VERSION 5.7 ;
  NOWIREEXTENSIONATPIN ON ;
  DIVIDERCHAR "/" ;
  BUSBITCHARS "[]" ;
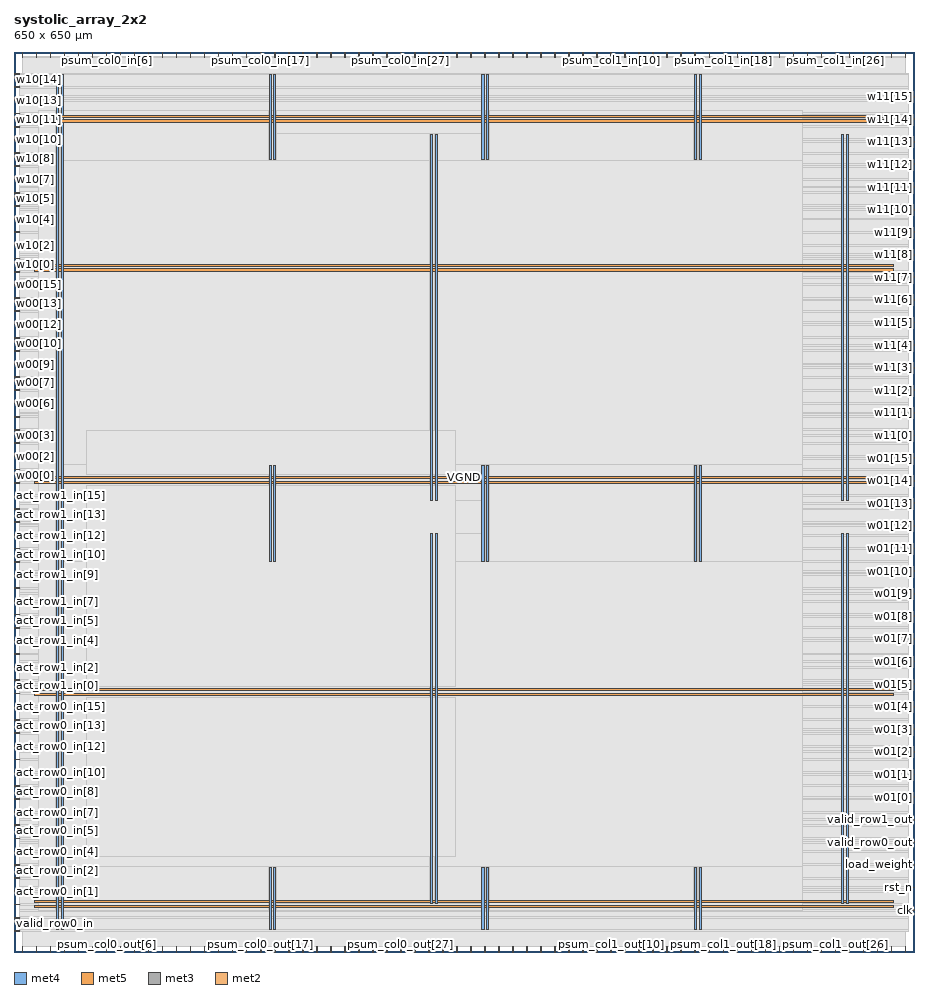
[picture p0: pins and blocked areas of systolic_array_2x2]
MACRO systolic_array_2x2
  CLASS BLOCK ;
  FOREIGN systolic_array_2x2 ;
  ORIGIN 0.000 0.000 ;
  SIZE 650.000 BY 650.000 ;
  PIN VGND
    DIRECTION INOUT ;
    USE GROUND ;
    PORT
      LAYER met4 ;
        RECT 34.000 16.080 35.600 634.000 ;
    END
    PORT
      LAYER met4 ;
        RECT 187.600 16.080 189.200 61.335 ;
    END
    PORT
      LAYER met4 ;
        RECT 187.600 282.105 189.200 351.335 ;
    END
    PORT
      LAYER met4 ;
        RECT 187.600 572.105 189.200 634.000 ;
    END
    PORT
      LAYER met4 ;
        RECT 341.200 16.080 342.800 61.335 ;
    END
    PORT
      LAYER met4 ;
        RECT 341.200 282.105 342.800 351.335 ;
    END
    PORT
      LAYER met4 ;
        RECT 341.200 572.105 342.800 634.000 ;
    END
    PORT
      LAYER met4 ;
        RECT 494.800 16.080 496.400 61.335 ;
    END
    PORT
      LAYER met4 ;
        RECT 494.800 282.105 496.400 351.335 ;
    END
    PORT
      LAYER met4 ;
        RECT 494.800 572.105 496.400 634.000 ;
    END
    PORT
      LAYER met5 ;
        RECT 14.940 35.470 635.040 37.070 ;
    END
    PORT
      LAYER met5 ;
        RECT 14.940 188.650 635.040 190.250 ;
    END
    PORT
      LAYER met5 ;
        RECT 14.940 341.830 635.040 343.430 ;
    END
    PORT
      LAYER met5 ;
        RECT 14.940 495.010 635.040 496.610 ;
    END
    PORT
      LAYER met4 ;
        RECT 304.180 35.120 305.780 302.160 ;
    END
    PORT
      LAYER met4 ;
        RECT 601.340 326.160 602.940 590.480 ;
    END
    PORT
      LAYER met4 ;
        RECT 304.180 326.160 305.780 590.480 ;
    END
    PORT
      LAYER met4 ;
        RECT 601.340 35.120 602.940 302.160 ;
    END
    PORT
      LAYER met5 ;
        RECT 30.700 602.700 635.040 604.300 ;
    END
  END VGND
  PIN VPWR
    DIRECTION INOUT ;
    USE POWER ;
    PORT
      LAYER met4 ;
        RECT 30.700 16.080 32.300 634.000 ;
    END
    PORT
      LAYER met4 ;
        RECT 184.300 16.080 185.900 61.335 ;
    END
    PORT
      LAYER met4 ;
        RECT 184.300 282.105 185.900 351.335 ;
    END
    PORT
      LAYER met4 ;
        RECT 184.300 572.105 185.900 634.000 ;
    END
    PORT
      LAYER met4 ;
        RECT 337.900 16.080 339.500 61.335 ;
    END
    PORT
      LAYER met4 ;
        RECT 337.900 282.105 339.500 351.335 ;
    END
    PORT
      LAYER met4 ;
        RECT 337.900 572.105 339.500 634.000 ;
    END
    PORT
      LAYER met4 ;
        RECT 491.500 16.080 493.100 61.335 ;
    END
    PORT
      LAYER met4 ;
        RECT 491.500 282.105 493.100 351.335 ;
    END
    PORT
      LAYER met4 ;
        RECT 491.500 572.105 493.100 634.000 ;
    END
    PORT
      LAYER met5 ;
        RECT 14.940 32.170 635.040 33.770 ;
    END
    PORT
      LAYER met5 ;
        RECT 14.940 185.350 635.040 186.950 ;
    END
    PORT
      LAYER met5 ;
        RECT 14.940 338.530 635.040 340.130 ;
    END
    PORT
      LAYER met5 ;
        RECT 14.940 491.710 635.040 493.310 ;
    END
    PORT
      LAYER met4 ;
        RECT 300.500 35.120 302.100 302.160 ;
    END
    PORT
      LAYER met4 ;
        RECT 597.660 326.160 599.260 590.480 ;
    END
    PORT
      LAYER met4 ;
        RECT 300.500 326.160 302.100 590.480 ;
    END
    PORT
      LAYER met4 ;
        RECT 597.660 35.120 599.260 302.160 ;
    END
    PORT
      LAYER met5 ;
        RECT 30.700 599.300 635.040 600.900 ;
    END
  END VPWR
  PIN act_row0_in[0]
    DIRECTION INPUT ;
    USE SIGNAL ;
    ANTENNAGATEAREA 0.647700 ;
    ANTENNADIFFAREA 0.434700 ;
    PORT
      LAYER met3 ;
        RECT 0.000 34.040 4.000 34.640 ;
    END
  END act_row0_in[0]
  PIN act_row0_in[10]
    DIRECTION INPUT ;
    USE SIGNAL ;
    ANTENNAGATEAREA 0.647700 ;
    ANTENNADIFFAREA 0.434700 ;
    PORT
      LAYER met3 ;
        RECT 0.000 129.240 4.000 129.840 ;
    END
  END act_row0_in[10]
  PIN act_row0_in[11]
    DIRECTION INPUT ;
    USE SIGNAL ;
    ANTENNAGATEAREA 0.647700 ;
    ANTENNADIFFAREA 0.434700 ;
    PORT
      LAYER met3 ;
        RECT 0.000 138.760 4.000 139.360 ;
    END
  END act_row0_in[11]
  PIN act_row0_in[12]
    DIRECTION INPUT ;
    USE SIGNAL ;
    ANTENNAGATEAREA 0.647700 ;
    ANTENNADIFFAREA 0.434700 ;
    PORT
      LAYER met3 ;
        RECT 0.000 148.280 4.000 148.880 ;
    END
  END act_row0_in[12]
  PIN act_row0_in[13]
    DIRECTION INPUT ;
    USE SIGNAL ;
    ANTENNAGATEAREA 0.647700 ;
    ANTENNADIFFAREA 0.434700 ;
    PORT
      LAYER met3 ;
        RECT 0.000 157.800 4.000 158.400 ;
    END
  END act_row0_in[13]
  PIN act_row0_in[14]
    DIRECTION INPUT ;
    USE SIGNAL ;
    ANTENNAGATEAREA 0.647700 ;
    ANTENNADIFFAREA 0.434700 ;
    PORT
      LAYER met3 ;
        RECT 0.000 167.320 4.000 167.920 ;
    END
  END act_row0_in[14]
  PIN act_row0_in[15]
    DIRECTION INPUT ;
    USE SIGNAL ;
    ANTENNAGATEAREA 0.647700 ;
    ANTENNADIFFAREA 0.434700 ;
    PORT
      LAYER met3 ;
        RECT 0.000 176.840 4.000 177.440 ;
    END
  END act_row0_in[15]
  PIN act_row0_in[1]
    DIRECTION INPUT ;
    USE SIGNAL ;
    ANTENNAGATEAREA 0.647700 ;
    ANTENNADIFFAREA 0.434700 ;
    PORT
      LAYER met3 ;
        RECT 0.000 43.560 4.000 44.160 ;
    END
  END act_row0_in[1]
  PIN act_row0_in[2]
    DIRECTION INPUT ;
    USE SIGNAL ;
    ANTENNAGATEAREA 0.647700 ;
    ANTENNADIFFAREA 0.434700 ;
    PORT
      LAYER met3 ;
        RECT 0.000 53.080 4.000 53.680 ;
    END
  END act_row0_in[2]
  PIN act_row0_in[3]
    DIRECTION INPUT ;
    USE SIGNAL ;
    ANTENNAGATEAREA 0.647700 ;
    ANTENNADIFFAREA 0.434700 ;
    PORT
      LAYER met3 ;
        RECT 0.000 62.600 4.000 63.200 ;
    END
  END act_row0_in[3]
  PIN act_row0_in[4]
    DIRECTION INPUT ;
    USE SIGNAL ;
    ANTENNAGATEAREA 0.647700 ;
    ANTENNADIFFAREA 0.434700 ;
    PORT
      LAYER met3 ;
        RECT 0.000 72.120 4.000 72.720 ;
    END
  END act_row0_in[4]
  PIN act_row0_in[5]
    DIRECTION INPUT ;
    USE SIGNAL ;
    ANTENNAGATEAREA 0.647700 ;
    ANTENNADIFFAREA 0.434700 ;
    PORT
      LAYER met3 ;
        RECT 0.000 81.640 4.000 82.240 ;
    END
  END act_row0_in[5]
  PIN act_row0_in[6]
    DIRECTION INPUT ;
    USE SIGNAL ;
    ANTENNAGATEAREA 0.647700 ;
    ANTENNADIFFAREA 0.434700 ;
    PORT
      LAYER met3 ;
        RECT 0.000 91.160 4.000 91.760 ;
    END
  END act_row0_in[6]
  PIN act_row0_in[7]
    DIRECTION INPUT ;
    USE SIGNAL ;
    ANTENNAGATEAREA 0.647700 ;
    ANTENNADIFFAREA 0.434700 ;
    PORT
      LAYER met3 ;
        RECT 0.000 100.680 4.000 101.280 ;
    END
  END act_row0_in[7]
  PIN act_row0_in[8]
    DIRECTION INPUT ;
    USE SIGNAL ;
    ANTENNAGATEAREA 0.647700 ;
    ANTENNADIFFAREA 0.434700 ;
    PORT
      LAYER met3 ;
        RECT 0.000 110.200 4.000 110.800 ;
    END
  END act_row0_in[8]
  PIN act_row0_in[9]
    DIRECTION INPUT ;
    USE SIGNAL ;
    ANTENNAGATEAREA 0.647700 ;
    ANTENNADIFFAREA 0.434700 ;
    PORT
      LAYER met3 ;
        RECT 0.000 119.720 4.000 120.320 ;
    END
  END act_row0_in[9]
  PIN act_row1_in[0]
    DIRECTION INPUT ;
    USE SIGNAL ;
    ANTENNAGATEAREA 0.631200 ;
    ANTENNADIFFAREA 0.434700 ;
    PORT
      LAYER met3 ;
        RECT 0.000 186.360 4.000 186.960 ;
    END
  END act_row1_in[0]
  PIN act_row1_in[10]
    DIRECTION INPUT ;
    USE SIGNAL ;
    ANTENNAGATEAREA 0.631200 ;
    ANTENNADIFFAREA 0.434700 ;
    PORT
      LAYER met3 ;
        RECT 0.000 281.560 4.000 282.160 ;
    END
  END act_row1_in[10]
  PIN act_row1_in[11]
    DIRECTION INPUT ;
    USE SIGNAL ;
    ANTENNAGATEAREA 0.631200 ;
    ANTENNADIFFAREA 0.434700 ;
    PORT
      LAYER met3 ;
        RECT 0.000 291.080 4.000 291.680 ;
    END
  END act_row1_in[11]
  PIN act_row1_in[12]
    DIRECTION INPUT ;
    USE SIGNAL ;
    ANTENNAGATEAREA 0.631200 ;
    ANTENNADIFFAREA 0.434700 ;
    PORT
      LAYER met3 ;
        RECT 0.000 300.600 4.000 301.200 ;
    END
  END act_row1_in[12]
  PIN act_row1_in[13]
    DIRECTION INPUT ;
    USE SIGNAL ;
    ANTENNAGATEAREA 0.631200 ;
    ANTENNADIFFAREA 0.434700 ;
    PORT
      LAYER met3 ;
        RECT 0.000 310.120 4.000 310.720 ;
    END
  END act_row1_in[13]
  PIN act_row1_in[14]
    DIRECTION INPUT ;
    USE SIGNAL ;
    ANTENNAGATEAREA 0.631200 ;
    ANTENNADIFFAREA 0.434700 ;
    PORT
      LAYER met3 ;
        RECT 0.000 319.640 4.000 320.240 ;
    END
  END act_row1_in[14]
  PIN act_row1_in[15]
    DIRECTION INPUT ;
    USE SIGNAL ;
    ANTENNAGATEAREA 0.560700 ;
    ANTENNADIFFAREA 0.434700 ;
    PORT
      LAYER met3 ;
        RECT 0.000 329.160 4.000 329.760 ;
    END
  END act_row1_in[15]
  PIN act_row1_in[1]
    DIRECTION INPUT ;
    USE SIGNAL ;
    ANTENNAGATEAREA 0.631200 ;
    ANTENNADIFFAREA 0.434700 ;
    PORT
      LAYER met3 ;
        RECT 0.000 195.880 4.000 196.480 ;
    END
  END act_row1_in[1]
  PIN act_row1_in[2]
    DIRECTION INPUT ;
    USE SIGNAL ;
    ANTENNAGATEAREA 0.631200 ;
    ANTENNADIFFAREA 0.434700 ;
    PORT
      LAYER met3 ;
        RECT 0.000 205.400 4.000 206.000 ;
    END
  END act_row1_in[2]
  PIN act_row1_in[3]
    DIRECTION INPUT ;
    USE SIGNAL ;
    ANTENNAGATEAREA 0.631200 ;
    ANTENNADIFFAREA 0.434700 ;
    PORT
      LAYER met3 ;
        RECT 0.000 214.920 4.000 215.520 ;
    END
  END act_row1_in[3]
  PIN act_row1_in[4]
    DIRECTION INPUT ;
    USE SIGNAL ;
    ANTENNAGATEAREA 0.631200 ;
    ANTENNADIFFAREA 0.434700 ;
    PORT
      LAYER met3 ;
        RECT 0.000 224.440 4.000 225.040 ;
    END
  END act_row1_in[4]
  PIN act_row1_in[5]
    DIRECTION INPUT ;
    USE SIGNAL ;
    ANTENNAGATEAREA 0.631200 ;
    ANTENNADIFFAREA 0.434700 ;
    PORT
      LAYER met3 ;
        RECT 0.000 233.960 4.000 234.560 ;
    END
  END act_row1_in[5]
  PIN act_row1_in[6]
    DIRECTION INPUT ;
    USE SIGNAL ;
    ANTENNAGATEAREA 0.631200 ;
    ANTENNADIFFAREA 0.434700 ;
    PORT
      LAYER met3 ;
        RECT 0.000 243.480 4.000 244.080 ;
    END
  END act_row1_in[6]
  PIN act_row1_in[7]
    DIRECTION INPUT ;
    USE SIGNAL ;
    ANTENNAGATEAREA 0.631200 ;
    ANTENNADIFFAREA 0.434700 ;
    PORT
      LAYER met3 ;
        RECT 0.000 253.000 4.000 253.600 ;
    END
  END act_row1_in[7]
  PIN act_row1_in[8]
    DIRECTION INPUT ;
    USE SIGNAL ;
    ANTENNAGATEAREA 0.631200 ;
    ANTENNADIFFAREA 0.434700 ;
    PORT
      LAYER met3 ;
        RECT 0.000 262.520 4.000 263.120 ;
    END
  END act_row1_in[8]
  PIN act_row1_in[9]
    DIRECTION INPUT ;
    USE SIGNAL ;
    ANTENNAGATEAREA 0.631200 ;
    ANTENNADIFFAREA 0.434700 ;
    PORT
      LAYER met3 ;
        RECT 0.000 272.040 4.000 272.640 ;
    END
  END act_row1_in[9]
  PIN clk
    DIRECTION INPUT ;
    USE SIGNAL ;
    ANTENNAGATEAREA 1.286700 ;
    ANTENNADIFFAREA 0.434700 ;
    PORT
      LAYER met3 ;
        RECT 646.000 29.960 650.000 30.560 ;
    END
  END clk
  PIN load_weight
    DIRECTION INPUT ;
    USE SIGNAL ;
    ANTENNAGATEAREA 1.286700 ;
    ANTENNADIFFAREA 0.434700 ;
    PORT
      LAYER met3 ;
        RECT 646.000 62.600 650.000 63.200 ;
    END
  END load_weight
  PIN psum_col0_in[0]
    DIRECTION INPUT ;
    USE SIGNAL ;
    ANTENNAGATEAREA 0.631200 ;
    ANTENNADIFFAREA 0.434700 ;
    PORT
      LAYER met2 ;
        RECT 6.070 646.000 6.350 650.000 ;
    END
  END psum_col0_in[0]
  PIN psum_col0_in[10]
    DIRECTION INPUT ;
    USE SIGNAL ;
    ANTENNAGATEAREA 0.631200 ;
    ANTENNADIFFAREA 0.434700 ;
    PORT
      LAYER met2 ;
        RECT 107.270 646.000 107.550 650.000 ;
    END
  END psum_col0_in[10]
  PIN psum_col0_in[11]
    DIRECTION INPUT ;
    USE SIGNAL ;
    ANTENNAGATEAREA 0.631200 ;
    ANTENNADIFFAREA 0.434700 ;
    PORT
      LAYER met2 ;
        RECT 117.390 646.000 117.670 650.000 ;
    END
  END psum_col0_in[11]
  PIN psum_col0_in[12]
    DIRECTION INPUT ;
    USE SIGNAL ;
    ANTENNAGATEAREA 0.631200 ;
    ANTENNADIFFAREA 0.434700 ;
    PORT
      LAYER met2 ;
        RECT 127.510 646.000 127.790 650.000 ;
    END
  END psum_col0_in[12]
  PIN psum_col0_in[13]
    DIRECTION INPUT ;
    USE SIGNAL ;
    ANTENNAGATEAREA 0.631200 ;
    ANTENNADIFFAREA 0.434700 ;
    PORT
      LAYER met2 ;
        RECT 137.630 646.000 137.910 650.000 ;
    END
  END psum_col0_in[13]
  PIN psum_col0_in[14]
    DIRECTION INPUT ;
    USE SIGNAL ;
    ANTENNAGATEAREA 0.631200 ;
    ANTENNADIFFAREA 0.434700 ;
    PORT
      LAYER met2 ;
        RECT 147.750 646.000 148.030 650.000 ;
    END
  END psum_col0_in[14]
  PIN psum_col0_in[15]
    DIRECTION INPUT ;
    USE SIGNAL ;
    ANTENNAGATEAREA 0.631200 ;
    ANTENNADIFFAREA 0.434700 ;
    PORT
      LAYER met2 ;
        RECT 157.870 646.000 158.150 650.000 ;
    END
  END psum_col0_in[15]
  PIN psum_col0_in[16]
    DIRECTION INPUT ;
    USE SIGNAL ;
    ANTENNAGATEAREA 0.631200 ;
    ANTENNADIFFAREA 0.434700 ;
    PORT
      LAYER met2 ;
        RECT 167.990 646.000 168.270 650.000 ;
    END
  END psum_col0_in[16]
  PIN psum_col0_in[17]
    DIRECTION INPUT ;
    USE SIGNAL ;
    ANTENNAGATEAREA 0.631200 ;
    ANTENNADIFFAREA 0.434700 ;
    PORT
      LAYER met2 ;
        RECT 178.110 646.000 178.390 650.000 ;
    END
  END psum_col0_in[17]
  PIN psum_col0_in[18]
    DIRECTION INPUT ;
    USE SIGNAL ;
    ANTENNAGATEAREA 0.631200 ;
    ANTENNADIFFAREA 0.434700 ;
    PORT
      LAYER met2 ;
        RECT 188.230 646.000 188.510 650.000 ;
    END
  END psum_col0_in[18]
  PIN psum_col0_in[19]
    DIRECTION INPUT ;
    USE SIGNAL ;
    ANTENNAGATEAREA 0.631200 ;
    ANTENNADIFFAREA 0.434700 ;
    PORT
      LAYER met2 ;
        RECT 198.350 646.000 198.630 650.000 ;
    END
  END psum_col0_in[19]
  PIN psum_col0_in[1]
    DIRECTION INPUT ;
    USE SIGNAL ;
    ANTENNAGATEAREA 0.631200 ;
    ANTENNADIFFAREA 0.434700 ;
    PORT
      LAYER met2 ;
        RECT 16.190 646.000 16.470 650.000 ;
    END
  END psum_col0_in[1]
  PIN psum_col0_in[20]
    DIRECTION INPUT ;
    USE SIGNAL ;
    ANTENNAGATEAREA 0.631200 ;
    ANTENNADIFFAREA 0.434700 ;
    PORT
      LAYER met2 ;
        RECT 208.470 646.000 208.750 650.000 ;
    END
  END psum_col0_in[20]
  PIN psum_col0_in[21]
    DIRECTION INPUT ;
    USE SIGNAL ;
    ANTENNAGATEAREA 0.631200 ;
    ANTENNADIFFAREA 0.434700 ;
    PORT
      LAYER met2 ;
        RECT 218.590 646.000 218.870 650.000 ;
    END
  END psum_col0_in[21]
  PIN psum_col0_in[22]
    DIRECTION INPUT ;
    USE SIGNAL ;
    ANTENNAGATEAREA 0.631200 ;
    ANTENNADIFFAREA 0.434700 ;
    PORT
      LAYER met2 ;
        RECT 228.710 646.000 228.990 650.000 ;
    END
  END psum_col0_in[22]
  PIN psum_col0_in[23]
    DIRECTION INPUT ;
    USE SIGNAL ;
    ANTENNAGATEAREA 0.631200 ;
    ANTENNADIFFAREA 0.434700 ;
    PORT
      LAYER met2 ;
        RECT 238.830 646.000 239.110 650.000 ;
    END
  END psum_col0_in[23]
  PIN psum_col0_in[24]
    DIRECTION INPUT ;
    USE SIGNAL ;
    ANTENNAGATEAREA 0.631200 ;
    ANTENNADIFFAREA 0.434700 ;
    PORT
      LAYER met2 ;
        RECT 248.950 646.000 249.230 650.000 ;
    END
  END psum_col0_in[24]
  PIN psum_col0_in[25]
    DIRECTION INPUT ;
    USE SIGNAL ;
    ANTENNAGATEAREA 0.631200 ;
    ANTENNADIFFAREA 0.434700 ;
    PORT
      LAYER met2 ;
        RECT 259.070 646.000 259.350 650.000 ;
    END
  END psum_col0_in[25]
  PIN psum_col0_in[26]
    DIRECTION INPUT ;
    USE SIGNAL ;
    ANTENNAGATEAREA 0.631200 ;
    ANTENNADIFFAREA 0.434700 ;
    PORT
      LAYER met2 ;
        RECT 269.190 646.000 269.470 650.000 ;
    END
  END psum_col0_in[26]
  PIN psum_col0_in[27]
    DIRECTION INPUT ;
    USE SIGNAL ;
    ANTENNAGATEAREA 0.631200 ;
    ANTENNADIFFAREA 0.434700 ;
    PORT
      LAYER met2 ;
        RECT 279.310 646.000 279.590 650.000 ;
    END
  END psum_col0_in[27]
  PIN psum_col0_in[28]
    DIRECTION INPUT ;
    USE SIGNAL ;
    ANTENNAGATEAREA 0.631200 ;
    ANTENNADIFFAREA 0.434700 ;
    PORT
      LAYER met2 ;
        RECT 289.430 646.000 289.710 650.000 ;
    END
  END psum_col0_in[28]
  PIN psum_col0_in[29]
    DIRECTION INPUT ;
    USE SIGNAL ;
    ANTENNAGATEAREA 0.631200 ;
    ANTENNADIFFAREA 0.434700 ;
    PORT
      LAYER met2 ;
        RECT 299.550 646.000 299.830 650.000 ;
    END
  END psum_col0_in[29]
  PIN psum_col0_in[2]
    DIRECTION INPUT ;
    USE SIGNAL ;
    ANTENNAGATEAREA 0.631200 ;
    ANTENNADIFFAREA 0.434700 ;
    PORT
      LAYER met2 ;
        RECT 26.310 646.000 26.590 650.000 ;
    END
  END psum_col0_in[2]
  PIN psum_col0_in[30]
    DIRECTION INPUT ;
    USE SIGNAL ;
    ANTENNAGATEAREA 0.631200 ;
    ANTENNADIFFAREA 0.434700 ;
    PORT
      LAYER met2 ;
        RECT 309.670 646.000 309.950 650.000 ;
    END
  END psum_col0_in[30]
  PIN psum_col0_in[31]
    DIRECTION INPUT ;
    USE SIGNAL ;
    ANTENNAGATEAREA 0.631200 ;
    ANTENNADIFFAREA 0.434700 ;
    PORT
      LAYER met2 ;
        RECT 319.790 646.000 320.070 650.000 ;
    END
  END psum_col0_in[31]
  PIN psum_col0_in[3]
    DIRECTION INPUT ;
    USE SIGNAL ;
    ANTENNAGATEAREA 0.631200 ;
    ANTENNADIFFAREA 0.434700 ;
    PORT
      LAYER met2 ;
        RECT 36.430 646.000 36.710 650.000 ;
    END
  END psum_col0_in[3]
  PIN psum_col0_in[4]
    DIRECTION INPUT ;
    USE SIGNAL ;
    ANTENNAGATEAREA 0.631200 ;
    ANTENNADIFFAREA 0.434700 ;
    PORT
      LAYER met2 ;
        RECT 46.550 646.000 46.830 650.000 ;
    END
  END psum_col0_in[4]
  PIN psum_col0_in[5]
    DIRECTION INPUT ;
    USE SIGNAL ;
    ANTENNAGATEAREA 0.631200 ;
    ANTENNADIFFAREA 0.434700 ;
    PORT
      LAYER met2 ;
        RECT 56.670 646.000 56.950 650.000 ;
    END
  END psum_col0_in[5]
  PIN psum_col0_in[6]
    DIRECTION INPUT ;
    USE SIGNAL ;
    ANTENNAGATEAREA 0.631200 ;
    ANTENNADIFFAREA 0.434700 ;
    PORT
      LAYER met2 ;
        RECT 66.790 646.000 67.070 650.000 ;
    END
  END psum_col0_in[6]
  PIN psum_col0_in[7]
    DIRECTION INPUT ;
    USE SIGNAL ;
    ANTENNAGATEAREA 0.631200 ;
    ANTENNADIFFAREA 0.434700 ;
    PORT
      LAYER met2 ;
        RECT 76.910 646.000 77.190 650.000 ;
    END
  END psum_col0_in[7]
  PIN psum_col0_in[8]
    DIRECTION INPUT ;
    USE SIGNAL ;
    ANTENNAGATEAREA 0.631200 ;
    ANTENNADIFFAREA 0.434700 ;
    PORT
      LAYER met2 ;
        RECT 87.030 646.000 87.310 650.000 ;
    END
  END psum_col0_in[8]
  PIN psum_col0_in[9]
    DIRECTION INPUT ;
    USE SIGNAL ;
    ANTENNAGATEAREA 0.631200 ;
    ANTENNADIFFAREA 0.434700 ;
    PORT
      LAYER met2 ;
        RECT 97.150 646.000 97.430 650.000 ;
    END
  END psum_col0_in[9]
  PIN psum_col0_out[0]
    DIRECTION OUTPUT TRISTATE ;
    USE SIGNAL ;
    ANTENNADIFFAREA 0.795200 ;
    PORT
      LAYER met2 ;
        RECT 6.070 0.000 6.350 4.000 ;
    END
  END psum_col0_out[0]
  PIN psum_col0_out[10]
    DIRECTION OUTPUT TRISTATE ;
    USE SIGNAL ;
    ANTENNADIFFAREA 0.795200 ;
    PORT
      LAYER met2 ;
        RECT 107.270 0.000 107.550 4.000 ;
    END
  END psum_col0_out[10]
  PIN psum_col0_out[11]
    DIRECTION OUTPUT TRISTATE ;
    USE SIGNAL ;
    ANTENNADIFFAREA 0.795200 ;
    PORT
      LAYER met2 ;
        RECT 117.390 0.000 117.670 4.000 ;
    END
  END psum_col0_out[11]
  PIN psum_col0_out[12]
    DIRECTION OUTPUT TRISTATE ;
    USE SIGNAL ;
    ANTENNADIFFAREA 0.795200 ;
    PORT
      LAYER met2 ;
        RECT 127.510 0.000 127.790 4.000 ;
    END
  END psum_col0_out[12]
  PIN psum_col0_out[13]
    DIRECTION OUTPUT TRISTATE ;
    USE SIGNAL ;
    ANTENNADIFFAREA 0.795200 ;
    PORT
      LAYER met2 ;
        RECT 137.630 0.000 137.910 4.000 ;
    END
  END psum_col0_out[13]
  PIN psum_col0_out[14]
    DIRECTION OUTPUT TRISTATE ;
    USE SIGNAL ;
    ANTENNADIFFAREA 0.795200 ;
    PORT
      LAYER met2 ;
        RECT 147.750 0.000 148.030 4.000 ;
    END
  END psum_col0_out[14]
  PIN psum_col0_out[15]
    DIRECTION OUTPUT TRISTATE ;
    USE SIGNAL ;
    ANTENNADIFFAREA 0.795200 ;
    PORT
      LAYER met2 ;
        RECT 157.870 0.000 158.150 4.000 ;
    END
  END psum_col0_out[15]
  PIN psum_col0_out[16]
    DIRECTION OUTPUT TRISTATE ;
    USE SIGNAL ;
    ANTENNADIFFAREA 0.795200 ;
    PORT
      LAYER met2 ;
        RECT 167.990 0.000 168.270 4.000 ;
    END
  END psum_col0_out[16]
  PIN psum_col0_out[17]
    DIRECTION OUTPUT TRISTATE ;
    USE SIGNAL ;
    ANTENNADIFFAREA 0.795200 ;
    PORT
      LAYER met2 ;
        RECT 178.110 0.000 178.390 4.000 ;
    END
  END psum_col0_out[17]
  PIN psum_col0_out[18]
    DIRECTION OUTPUT TRISTATE ;
    USE SIGNAL ;
    ANTENNADIFFAREA 0.795200 ;
    PORT
      LAYER met2 ;
        RECT 188.230 0.000 188.510 4.000 ;
    END
  END psum_col0_out[18]
  PIN psum_col0_out[19]
    DIRECTION OUTPUT TRISTATE ;
    USE SIGNAL ;
    ANTENNADIFFAREA 0.795200 ;
    PORT
      LAYER met2 ;
        RECT 198.350 0.000 198.630 4.000 ;
    END
  END psum_col0_out[19]
  PIN psum_col0_out[1]
    DIRECTION OUTPUT TRISTATE ;
    USE SIGNAL ;
    ANTENNADIFFAREA 0.795200 ;
    PORT
      LAYER met2 ;
        RECT 16.190 0.000 16.470 4.000 ;
    END
  END psum_col0_out[1]
  PIN psum_col0_out[20]
    DIRECTION OUTPUT TRISTATE ;
    USE SIGNAL ;
    ANTENNADIFFAREA 0.795200 ;
    PORT
      LAYER met2 ;
        RECT 208.470 0.000 208.750 4.000 ;
    END
  END psum_col0_out[20]
  PIN psum_col0_out[21]
    DIRECTION OUTPUT TRISTATE ;
    USE SIGNAL ;
    ANTENNADIFFAREA 0.795200 ;
    PORT
      LAYER met2 ;
        RECT 218.590 0.000 218.870 4.000 ;
    END
  END psum_col0_out[21]
  PIN psum_col0_out[22]
    DIRECTION OUTPUT TRISTATE ;
    USE SIGNAL ;
    ANTENNADIFFAREA 0.795200 ;
    PORT
      LAYER met2 ;
        RECT 228.710 0.000 228.990 4.000 ;
    END
  END psum_col0_out[22]
  PIN psum_col0_out[23]
    DIRECTION OUTPUT TRISTATE ;
    USE SIGNAL ;
    ANTENNADIFFAREA 0.795200 ;
    PORT
      LAYER met2 ;
        RECT 238.830 0.000 239.110 4.000 ;
    END
  END psum_col0_out[23]
  PIN psum_col0_out[24]
    DIRECTION OUTPUT TRISTATE ;
    USE SIGNAL ;
    ANTENNADIFFAREA 0.795200 ;
    PORT
      LAYER met2 ;
        RECT 248.950 0.000 249.230 4.000 ;
    END
  END psum_col0_out[24]
  PIN psum_col0_out[25]
    DIRECTION OUTPUT TRISTATE ;
    USE SIGNAL ;
    ANTENNADIFFAREA 0.795200 ;
    PORT
      LAYER met2 ;
        RECT 259.070 0.000 259.350 4.000 ;
    END
  END psum_col0_out[25]
  PIN psum_col0_out[26]
    DIRECTION OUTPUT TRISTATE ;
    USE SIGNAL ;
    ANTENNADIFFAREA 0.795200 ;
    PORT
      LAYER met2 ;
        RECT 269.190 0.000 269.470 4.000 ;
    END
  END psum_col0_out[26]
  PIN psum_col0_out[27]
    DIRECTION OUTPUT TRISTATE ;
    USE SIGNAL ;
    ANTENNADIFFAREA 0.795200 ;
    PORT
      LAYER met2 ;
        RECT 279.310 0.000 279.590 4.000 ;
    END
  END psum_col0_out[27]
  PIN psum_col0_out[28]
    DIRECTION OUTPUT TRISTATE ;
    USE SIGNAL ;
    ANTENNADIFFAREA 0.795200 ;
    PORT
      LAYER met2 ;
        RECT 289.430 0.000 289.710 4.000 ;
    END
  END psum_col0_out[28]
  PIN psum_col0_out[29]
    DIRECTION OUTPUT TRISTATE ;
    USE SIGNAL ;
    ANTENNADIFFAREA 0.795200 ;
    PORT
      LAYER met2 ;
        RECT 299.550 0.000 299.830 4.000 ;
    END
  END psum_col0_out[29]
  PIN psum_col0_out[2]
    DIRECTION OUTPUT TRISTATE ;
    USE SIGNAL ;
    ANTENNADIFFAREA 0.795200 ;
    PORT
      LAYER met2 ;
        RECT 26.310 0.000 26.590 4.000 ;
    END
  END psum_col0_out[2]
  PIN psum_col0_out[30]
    DIRECTION OUTPUT TRISTATE ;
    USE SIGNAL ;
    ANTENNADIFFAREA 0.795200 ;
    PORT
      LAYER met2 ;
        RECT 309.670 0.000 309.950 4.000 ;
    END
  END psum_col0_out[30]
  PIN psum_col0_out[31]
    DIRECTION OUTPUT TRISTATE ;
    USE SIGNAL ;
    ANTENNADIFFAREA 0.795200 ;
    PORT
      LAYER met2 ;
        RECT 319.790 0.000 320.070 4.000 ;
    END
  END psum_col0_out[31]
  PIN psum_col0_out[3]
    DIRECTION OUTPUT TRISTATE ;
    USE SIGNAL ;
    ANTENNADIFFAREA 0.795200 ;
    PORT
      LAYER met2 ;
        RECT 36.430 0.000 36.710 4.000 ;
    END
  END psum_col0_out[3]
  PIN psum_col0_out[4]
    DIRECTION OUTPUT TRISTATE ;
    USE SIGNAL ;
    ANTENNADIFFAREA 0.795200 ;
    PORT
      LAYER met2 ;
        RECT 46.550 0.000 46.830 4.000 ;
    END
  END psum_col0_out[4]
  PIN psum_col0_out[5]
    DIRECTION OUTPUT TRISTATE ;
    USE SIGNAL ;
    ANTENNADIFFAREA 0.795200 ;
    PORT
      LAYER met2 ;
        RECT 56.670 0.000 56.950 4.000 ;
    END
  END psum_col0_out[5]
  PIN psum_col0_out[6]
    DIRECTION OUTPUT TRISTATE ;
    USE SIGNAL ;
    ANTENNADIFFAREA 0.795200 ;
    PORT
      LAYER met2 ;
        RECT 66.790 0.000 67.070 4.000 ;
    END
  END psum_col0_out[6]
  PIN psum_col0_out[7]
    DIRECTION OUTPUT TRISTATE ;
    USE SIGNAL ;
    ANTENNADIFFAREA 0.795200 ;
    PORT
      LAYER met2 ;
        RECT 76.910 0.000 77.190 4.000 ;
    END
  END psum_col0_out[7]
  PIN psum_col0_out[8]
    DIRECTION OUTPUT TRISTATE ;
    USE SIGNAL ;
    ANTENNADIFFAREA 0.795200 ;
    PORT
      LAYER met2 ;
        RECT 87.030 0.000 87.310 4.000 ;
    END
  END psum_col0_out[8]
  PIN psum_col0_out[9]
    DIRECTION OUTPUT TRISTATE ;
    USE SIGNAL ;
    ANTENNADIFFAREA 0.795200 ;
    PORT
      LAYER met2 ;
        RECT 97.150 0.000 97.430 4.000 ;
    END
  END psum_col0_out[9]
  PIN psum_col1_in[0]
    DIRECTION INPUT ;
    USE SIGNAL ;
    ANTENNAGATEAREA 0.631200 ;
    ANTENNADIFFAREA 0.434700 ;
    PORT
      LAYER met2 ;
        RECT 329.910 646.000 330.190 650.000 ;
    END
  END psum_col1_in[0]
  PIN psum_col1_in[10]
    DIRECTION INPUT ;
    USE SIGNAL ;
    ANTENNAGATEAREA 0.631200 ;
    ANTENNADIFFAREA 0.434700 ;
    PORT
      LAYER met2 ;
        RECT 431.110 646.000 431.390 650.000 ;
    END
  END psum_col1_in[10]
  PIN psum_col1_in[11]
    DIRECTION INPUT ;
    USE SIGNAL ;
    ANTENNAGATEAREA 0.631200 ;
    ANTENNADIFFAREA 0.434700 ;
    PORT
      LAYER met2 ;
        RECT 441.230 646.000 441.510 650.000 ;
    END
  END psum_col1_in[11]
  PIN psum_col1_in[12]
    DIRECTION INPUT ;
    USE SIGNAL ;
    ANTENNAGATEAREA 0.631200 ;
    ANTENNADIFFAREA 0.434700 ;
    PORT
      LAYER met2 ;
        RECT 451.350 646.000 451.630 650.000 ;
    END
  END psum_col1_in[12]
  PIN psum_col1_in[13]
    DIRECTION INPUT ;
    USE SIGNAL ;
    ANTENNAGATEAREA 0.631200 ;
    ANTENNADIFFAREA 0.434700 ;
    PORT
      LAYER met2 ;
        RECT 461.470 646.000 461.750 650.000 ;
    END
  END psum_col1_in[13]
  PIN psum_col1_in[14]
    DIRECTION INPUT ;
    USE SIGNAL ;
    ANTENNAGATEAREA 0.631200 ;
    ANTENNADIFFAREA 0.434700 ;
    PORT
      LAYER met2 ;
        RECT 471.590 646.000 471.870 650.000 ;
    END
  END psum_col1_in[14]
  PIN psum_col1_in[15]
    DIRECTION INPUT ;
    USE SIGNAL ;
    ANTENNAGATEAREA 0.631200 ;
    ANTENNADIFFAREA 0.434700 ;
    PORT
      LAYER met2 ;
        RECT 481.710 646.000 481.990 650.000 ;
    END
  END psum_col1_in[15]
  PIN psum_col1_in[16]
    DIRECTION INPUT ;
    USE SIGNAL ;
    ANTENNAGATEAREA 0.631200 ;
    ANTENNADIFFAREA 0.434700 ;
    PORT
      LAYER met2 ;
        RECT 491.830 646.000 492.110 650.000 ;
    END
  END psum_col1_in[16]
  PIN psum_col1_in[17]
    DIRECTION INPUT ;
    USE SIGNAL ;
    ANTENNAGATEAREA 0.631200 ;
    ANTENNADIFFAREA 0.434700 ;
    PORT
      LAYER met2 ;
        RECT 501.950 646.000 502.230 650.000 ;
    END
  END psum_col1_in[17]
  PIN psum_col1_in[18]
    DIRECTION INPUT ;
    USE SIGNAL ;
    ANTENNAGATEAREA 0.631200 ;
    ANTENNADIFFAREA 0.434700 ;
    PORT
      LAYER met2 ;
        RECT 512.070 646.000 512.350 650.000 ;
    END
  END psum_col1_in[18]
  PIN psum_col1_in[19]
    DIRECTION INPUT ;
    USE SIGNAL ;
    ANTENNAGATEAREA 0.631200 ;
    ANTENNADIFFAREA 0.434700 ;
    PORT
      LAYER met2 ;
        RECT 522.190 646.000 522.470 650.000 ;
    END
  END psum_col1_in[19]
  PIN psum_col1_in[1]
    DIRECTION INPUT ;
    USE SIGNAL ;
    ANTENNAGATEAREA 0.631200 ;
    ANTENNADIFFAREA 0.434700 ;
    PORT
      LAYER met2 ;
        RECT 340.030 646.000 340.310 650.000 ;
    END
  END psum_col1_in[1]
  PIN psum_col1_in[20]
    DIRECTION INPUT ;
    USE SIGNAL ;
    ANTENNAGATEAREA 0.560700 ;
    ANTENNADIFFAREA 0.434700 ;
    PORT
      LAYER met2 ;
        RECT 532.310 646.000 532.590 650.000 ;
    END
  END psum_col1_in[20]
  PIN psum_col1_in[21]
    DIRECTION INPUT ;
    USE SIGNAL ;
    ANTENNAGATEAREA 0.560700 ;
    ANTENNADIFFAREA 0.434700 ;
    PORT
      LAYER met2 ;
        RECT 542.430 646.000 542.710 650.000 ;
    END
  END psum_col1_in[21]
  PIN psum_col1_in[22]
    DIRECTION INPUT ;
    USE SIGNAL ;
    ANTENNAGATEAREA 0.560700 ;
    ANTENNADIFFAREA 0.434700 ;
    PORT
      LAYER met2 ;
        RECT 552.550 646.000 552.830 650.000 ;
    END
  END psum_col1_in[22]
  PIN psum_col1_in[23]
    DIRECTION INPUT ;
    USE SIGNAL ;
    ANTENNAGATEAREA 0.560700 ;
    ANTENNADIFFAREA 0.434700 ;
    PORT
      LAYER met2 ;
        RECT 562.670 646.000 562.950 650.000 ;
    END
  END psum_col1_in[23]
  PIN psum_col1_in[24]
    DIRECTION INPUT ;
    USE SIGNAL ;
    ANTENNAGATEAREA 0.560700 ;
    ANTENNADIFFAREA 0.434700 ;
    PORT
      LAYER met2 ;
        RECT 572.790 646.000 573.070 650.000 ;
    END
  END psum_col1_in[24]
  PIN psum_col1_in[25]
    DIRECTION INPUT ;
    USE SIGNAL ;
    ANTENNAGATEAREA 0.560700 ;
    ANTENNADIFFAREA 0.434700 ;
    PORT
      LAYER met2 ;
        RECT 582.910 646.000 583.190 650.000 ;
    END
  END psum_col1_in[25]
  PIN psum_col1_in[26]
    DIRECTION INPUT ;
    USE SIGNAL ;
    ANTENNAGATEAREA 0.560700 ;
    ANTENNADIFFAREA 0.434700 ;
    PORT
      LAYER met2 ;
        RECT 593.030 646.000 593.310 650.000 ;
    END
  END psum_col1_in[26]
  PIN psum_col1_in[27]
    DIRECTION INPUT ;
    USE SIGNAL ;
    ANTENNAGATEAREA 0.560700 ;
    ANTENNADIFFAREA 0.434700 ;
    PORT
      LAYER met2 ;
        RECT 603.150 646.000 603.430 650.000 ;
    END
  END psum_col1_in[27]
  PIN psum_col1_in[28]
    DIRECTION INPUT ;
    USE SIGNAL ;
    ANTENNAGATEAREA 0.647700 ;
    ANTENNADIFFAREA 0.434700 ;
    PORT
      LAYER met2 ;
        RECT 613.270 646.000 613.550 650.000 ;
    END
  END psum_col1_in[28]
  PIN psum_col1_in[29]
    DIRECTION INPUT ;
    USE SIGNAL ;
    ANTENNAGATEAREA 0.647700 ;
    ANTENNADIFFAREA 0.434700 ;
    PORT
      LAYER met2 ;
        RECT 623.390 646.000 623.670 650.000 ;
    END
  END psum_col1_in[29]
  PIN psum_col1_in[2]
    DIRECTION INPUT ;
    USE SIGNAL ;
    ANTENNAGATEAREA 0.631200 ;
    ANTENNADIFFAREA 0.434700 ;
    PORT
      LAYER met2 ;
        RECT 350.150 646.000 350.430 650.000 ;
    END
  END psum_col1_in[2]
  PIN psum_col1_in[30]
    DIRECTION INPUT ;
    USE SIGNAL ;
    ANTENNAGATEAREA 0.647700 ;
    ANTENNADIFFAREA 0.434700 ;
    PORT
      LAYER met2 ;
        RECT 633.510 646.000 633.790 650.000 ;
    END
  END psum_col1_in[30]
  PIN psum_col1_in[31]
    DIRECTION INPUT ;
    USE SIGNAL ;
    ANTENNAGATEAREA 0.647700 ;
    ANTENNADIFFAREA 0.434700 ;
    PORT
      LAYER met2 ;
        RECT 643.630 646.000 643.910 650.000 ;
    END
  END psum_col1_in[31]
  PIN psum_col1_in[3]
    DIRECTION INPUT ;
    USE SIGNAL ;
    ANTENNAGATEAREA 0.631200 ;
    ANTENNADIFFAREA 0.434700 ;
    PORT
      LAYER met2 ;
        RECT 360.270 646.000 360.550 650.000 ;
    END
  END psum_col1_in[3]
  PIN psum_col1_in[4]
    DIRECTION INPUT ;
    USE SIGNAL ;
    ANTENNAGATEAREA 0.631200 ;
    ANTENNADIFFAREA 0.434700 ;
    PORT
      LAYER met2 ;
        RECT 370.390 646.000 370.670 650.000 ;
    END
  END psum_col1_in[4]
  PIN psum_col1_in[5]
    DIRECTION INPUT ;
    USE SIGNAL ;
    ANTENNAGATEAREA 0.631200 ;
    ANTENNADIFFAREA 0.434700 ;
    PORT
      LAYER met2 ;
        RECT 380.510 646.000 380.790 650.000 ;
    END
  END psum_col1_in[5]
  PIN psum_col1_in[6]
    DIRECTION INPUT ;
    USE SIGNAL ;
    ANTENNAGATEAREA 0.631200 ;
    ANTENNADIFFAREA 0.434700 ;
    PORT
      LAYER met2 ;
        RECT 390.630 646.000 390.910 650.000 ;
    END
  END psum_col1_in[6]
  PIN psum_col1_in[7]
    DIRECTION INPUT ;
    USE SIGNAL ;
    ANTENNAGATEAREA 0.631200 ;
    ANTENNADIFFAREA 0.434700 ;
    PORT
      LAYER met2 ;
        RECT 400.750 646.000 401.030 650.000 ;
    END
  END psum_col1_in[7]
  PIN psum_col1_in[8]
    DIRECTION INPUT ;
    USE SIGNAL ;
    ANTENNAGATEAREA 0.631200 ;
    ANTENNADIFFAREA 0.434700 ;
    PORT
      LAYER met2 ;
        RECT 410.870 646.000 411.150 650.000 ;
    END
  END psum_col1_in[8]
  PIN psum_col1_in[9]
    DIRECTION INPUT ;
    USE SIGNAL ;
    ANTENNAGATEAREA 0.631200 ;
    ANTENNADIFFAREA 0.434700 ;
    PORT
      LAYER met2 ;
        RECT 420.990 646.000 421.270 650.000 ;
    END
  END psum_col1_in[9]
  PIN psum_col1_out[0]
    DIRECTION OUTPUT TRISTATE ;
    USE SIGNAL ;
    ANTENNADIFFAREA 0.795200 ;
    PORT
      LAYER met2 ;
        RECT 329.910 0.000 330.190 4.000 ;
    END
  END psum_col1_out[0]
  PIN psum_col1_out[10]
    DIRECTION OUTPUT TRISTATE ;
    USE SIGNAL ;
    ANTENNADIFFAREA 0.795200 ;
    PORT
      LAYER met2 ;
        RECT 431.110 0.000 431.390 4.000 ;
    END
  END psum_col1_out[10]
  PIN psum_col1_out[11]
    DIRECTION OUTPUT TRISTATE ;
    USE SIGNAL ;
    ANTENNADIFFAREA 0.795200 ;
    PORT
      LAYER met2 ;
        RECT 441.230 0.000 441.510 4.000 ;
    END
  END psum_col1_out[11]
  PIN psum_col1_out[12]
    DIRECTION OUTPUT TRISTATE ;
    USE SIGNAL ;
    ANTENNADIFFAREA 0.795200 ;
    PORT
      LAYER met2 ;
        RECT 451.350 0.000 451.630 4.000 ;
    END
  END psum_col1_out[12]
  PIN psum_col1_out[13]
    DIRECTION OUTPUT TRISTATE ;
    USE SIGNAL ;
    ANTENNADIFFAREA 0.795200 ;
    PORT
      LAYER met2 ;
        RECT 461.470 0.000 461.750 4.000 ;
    END
  END psum_col1_out[13]
  PIN psum_col1_out[14]
    DIRECTION OUTPUT TRISTATE ;
    USE SIGNAL ;
    ANTENNADIFFAREA 0.795200 ;
    PORT
      LAYER met2 ;
        RECT 471.590 0.000 471.870 4.000 ;
    END
  END psum_col1_out[14]
  PIN psum_col1_out[15]
    DIRECTION OUTPUT TRISTATE ;
    USE SIGNAL ;
    ANTENNADIFFAREA 0.795200 ;
    PORT
      LAYER met2 ;
        RECT 481.710 0.000 481.990 4.000 ;
    END
  END psum_col1_out[15]
  PIN psum_col1_out[16]
    DIRECTION OUTPUT TRISTATE ;
    USE SIGNAL ;
    ANTENNADIFFAREA 0.795200 ;
    PORT
      LAYER met2 ;
        RECT 491.830 0.000 492.110 4.000 ;
    END
  END psum_col1_out[16]
  PIN psum_col1_out[17]
    DIRECTION OUTPUT TRISTATE ;
    USE SIGNAL ;
    ANTENNADIFFAREA 0.795200 ;
    PORT
      LAYER met2 ;
        RECT 501.950 0.000 502.230 4.000 ;
    END
  END psum_col1_out[17]
  PIN psum_col1_out[18]
    DIRECTION OUTPUT TRISTATE ;
    USE SIGNAL ;
    ANTENNADIFFAREA 0.795200 ;
    PORT
      LAYER met2 ;
        RECT 512.070 0.000 512.350 4.000 ;
    END
  END psum_col1_out[18]
  PIN psum_col1_out[19]
    DIRECTION OUTPUT TRISTATE ;
    USE SIGNAL ;
    ANTENNADIFFAREA 0.795200 ;
    PORT
      LAYER met2 ;
        RECT 522.190 0.000 522.470 4.000 ;
    END
  END psum_col1_out[19]
  PIN psum_col1_out[1]
    DIRECTION OUTPUT TRISTATE ;
    USE SIGNAL ;
    ANTENNADIFFAREA 0.795200 ;
    PORT
      LAYER met2 ;
        RECT 340.030 0.000 340.310 4.000 ;
    END
  END psum_col1_out[1]
  PIN psum_col1_out[20]
    DIRECTION OUTPUT TRISTATE ;
    USE SIGNAL ;
    ANTENNADIFFAREA 0.795200 ;
    PORT
      LAYER met2 ;
        RECT 532.310 0.000 532.590 4.000 ;
    END
  END psum_col1_out[20]
  PIN psum_col1_out[21]
    DIRECTION OUTPUT TRISTATE ;
    USE SIGNAL ;
    ANTENNADIFFAREA 0.795200 ;
    PORT
      LAYER met2 ;
        RECT 542.430 0.000 542.710 4.000 ;
    END
  END psum_col1_out[21]
  PIN psum_col1_out[22]
    DIRECTION OUTPUT TRISTATE ;
    USE SIGNAL ;
    ANTENNADIFFAREA 0.795200 ;
    PORT
      LAYER met2 ;
        RECT 552.550 0.000 552.830 4.000 ;
    END
  END psum_col1_out[22]
  PIN psum_col1_out[23]
    DIRECTION OUTPUT TRISTATE ;
    USE SIGNAL ;
    ANTENNADIFFAREA 0.795200 ;
    PORT
      LAYER met2 ;
        RECT 562.670 0.000 562.950 4.000 ;
    END
  END psum_col1_out[23]
  PIN psum_col1_out[24]
    DIRECTION OUTPUT TRISTATE ;
    USE SIGNAL ;
    ANTENNADIFFAREA 0.795200 ;
    PORT
      LAYER met2 ;
        RECT 572.790 0.000 573.070 4.000 ;
    END
  END psum_col1_out[24]
  PIN psum_col1_out[25]
    DIRECTION OUTPUT TRISTATE ;
    USE SIGNAL ;
    ANTENNADIFFAREA 0.795200 ;
    PORT
      LAYER met2 ;
        RECT 582.910 0.000 583.190 4.000 ;
    END
  END psum_col1_out[25]
  PIN psum_col1_out[26]
    DIRECTION OUTPUT TRISTATE ;
    USE SIGNAL ;
    ANTENNADIFFAREA 0.795200 ;
    PORT
      LAYER met2 ;
        RECT 593.030 0.000 593.310 4.000 ;
    END
  END psum_col1_out[26]
  PIN psum_col1_out[27]
    DIRECTION OUTPUT TRISTATE ;
    USE SIGNAL ;
    ANTENNADIFFAREA 0.795200 ;
    PORT
      LAYER met2 ;
        RECT 603.150 0.000 603.430 4.000 ;
    END
  END psum_col1_out[27]
  PIN psum_col1_out[28]
    DIRECTION OUTPUT TRISTATE ;
    USE SIGNAL ;
    ANTENNADIFFAREA 0.795200 ;
    PORT
      LAYER met2 ;
        RECT 613.270 0.000 613.550 4.000 ;
    END
  END psum_col1_out[28]
  PIN psum_col1_out[29]
    DIRECTION OUTPUT TRISTATE ;
    USE SIGNAL ;
    ANTENNADIFFAREA 0.795200 ;
    PORT
      LAYER met2 ;
        RECT 623.390 0.000 623.670 4.000 ;
    END
  END psum_col1_out[29]
  PIN psum_col1_out[2]
    DIRECTION OUTPUT TRISTATE ;
    USE SIGNAL ;
    ANTENNADIFFAREA 0.795200 ;
    PORT
      LAYER met2 ;
        RECT 350.150 0.000 350.430 4.000 ;
    END
  END psum_col1_out[2]
  PIN psum_col1_out[30]
    DIRECTION OUTPUT TRISTATE ;
    USE SIGNAL ;
    ANTENNADIFFAREA 0.795200 ;
    PORT
      LAYER met2 ;
        RECT 633.510 0.000 633.790 4.000 ;
    END
  END psum_col1_out[30]
  PIN psum_col1_out[31]
    DIRECTION OUTPUT TRISTATE ;
    USE SIGNAL ;
    ANTENNADIFFAREA 0.795200 ;
    PORT
      LAYER met2 ;
        RECT 643.630 0.000 643.910 4.000 ;
    END
  END psum_col1_out[31]
  PIN psum_col1_out[3]
    DIRECTION OUTPUT TRISTATE ;
    USE SIGNAL ;
    ANTENNADIFFAREA 0.795200 ;
    PORT
      LAYER met2 ;
        RECT 360.270 0.000 360.550 4.000 ;
    END
  END psum_col1_out[3]
  PIN psum_col1_out[4]
    DIRECTION OUTPUT TRISTATE ;
    USE SIGNAL ;
    ANTENNADIFFAREA 0.795200 ;
    PORT
      LAYER met2 ;
        RECT 370.390 0.000 370.670 4.000 ;
    END
  END psum_col1_out[4]
  PIN psum_col1_out[5]
    DIRECTION OUTPUT TRISTATE ;
    USE SIGNAL ;
    ANTENNADIFFAREA 0.795200 ;
    PORT
      LAYER met2 ;
        RECT 380.510 0.000 380.790 4.000 ;
    END
  END psum_col1_out[5]
  PIN psum_col1_out[6]
    DIRECTION OUTPUT TRISTATE ;
    USE SIGNAL ;
    ANTENNADIFFAREA 0.795200 ;
    PORT
      LAYER met2 ;
        RECT 390.630 0.000 390.910 4.000 ;
    END
  END psum_col1_out[6]
  PIN psum_col1_out[7]
    DIRECTION OUTPUT TRISTATE ;
    USE SIGNAL ;
    ANTENNADIFFAREA 0.795200 ;
    PORT
      LAYER met2 ;
        RECT 400.750 0.000 401.030 4.000 ;
    END
  END psum_col1_out[7]
  PIN psum_col1_out[8]
    DIRECTION OUTPUT TRISTATE ;
    USE SIGNAL ;
    ANTENNADIFFAREA 0.795200 ;
    PORT
      LAYER met2 ;
        RECT 410.870 0.000 411.150 4.000 ;
    END
  END psum_col1_out[8]
  PIN psum_col1_out[9]
    DIRECTION OUTPUT TRISTATE ;
    USE SIGNAL ;
    ANTENNADIFFAREA 0.795200 ;
    PORT
      LAYER met2 ;
        RECT 420.990 0.000 421.270 4.000 ;
    END
  END psum_col1_out[9]
  PIN rst_n
    DIRECTION INPUT ;
    USE SIGNAL ;
    ANTENNAGATEAREA 1.286700 ;
    ANTENNADIFFAREA 0.434700 ;
    PORT
      LAYER met3 ;
        RECT 646.000 46.280 650.000 46.880 ;
    END
  END rst_n
  PIN valid_row0_in
    DIRECTION INPUT ;
    USE SIGNAL ;
    ANTENNAGATEAREA 0.647700 ;
    ANTENNADIFFAREA 0.434700 ;
    PORT
      LAYER met3 ;
        RECT 0.000 15.000 4.000 15.600 ;
    END
  END valid_row0_in
  PIN valid_row0_out
    DIRECTION OUTPUT TRISTATE ;
    USE SIGNAL ;
    ANTENNADIFFAREA 0.795200 ;
    PORT
      LAYER met3 ;
        RECT 646.000 78.920 650.000 79.520 ;
    END
  END valid_row0_out
  PIN valid_row1_in
    DIRECTION INPUT ;
    USE SIGNAL ;
    ANTENNAGATEAREA 0.647700 ;
    ANTENNADIFFAREA 0.434700 ;
    PORT
      LAYER met3 ;
        RECT 0.000 24.520 4.000 25.120 ;
    END
  END valid_row1_in
  PIN valid_row1_out
    DIRECTION OUTPUT TRISTATE ;
    USE SIGNAL ;
    ANTENNADIFFAREA 0.795200 ;
    PORT
      LAYER met3 ;
        RECT 646.000 95.240 650.000 95.840 ;
    END
  END valid_row1_out
  PIN w00[0]
    DIRECTION INPUT ;
    USE SIGNAL ;
    ANTENNAGATEAREA 0.631200 ;
    ANTENNADIFFAREA 0.434700 ;
    PORT
      LAYER met3 ;
        RECT 0.000 338.680 4.000 339.280 ;
    END
  END w00[0]
  PIN w00[10]
    DIRECTION INPUT ;
    USE SIGNAL ;
    ANTENNAGATEAREA 0.631200 ;
    ANTENNADIFFAREA 0.434700 ;
    PORT
      LAYER met3 ;
        RECT 0.000 433.880 4.000 434.480 ;
    END
  END w00[10]
  PIN w00[11]
    DIRECTION INPUT ;
    USE SIGNAL ;
    ANTENNAGATEAREA 0.631200 ;
    ANTENNADIFFAREA 0.434700 ;
    PORT
      LAYER met3 ;
        RECT 0.000 443.400 4.000 444.000 ;
    END
  END w00[11]
  PIN w00[12]
    DIRECTION INPUT ;
    USE SIGNAL ;
    ANTENNAGATEAREA 0.631200 ;
    ANTENNADIFFAREA 0.434700 ;
    PORT
      LAYER met3 ;
        RECT 0.000 452.920 4.000 453.520 ;
    END
  END w00[12]
  PIN w00[13]
    DIRECTION INPUT ;
    USE SIGNAL ;
    ANTENNAGATEAREA 0.631200 ;
    ANTENNADIFFAREA 0.434700 ;
    PORT
      LAYER met3 ;
        RECT 0.000 462.440 4.000 463.040 ;
    END
  END w00[13]
  PIN w00[14]
    DIRECTION INPUT ;
    USE SIGNAL ;
    ANTENNAGATEAREA 0.631200 ;
    ANTENNADIFFAREA 0.434700 ;
    PORT
      LAYER met3 ;
        RECT 0.000 471.960 4.000 472.560 ;
    END
  END w00[14]
  PIN w00[15]
    DIRECTION INPUT ;
    USE SIGNAL ;
    ANTENNAGATEAREA 0.631200 ;
    ANTENNADIFFAREA 0.434700 ;
    PORT
      LAYER met3 ;
        RECT 0.000 481.480 4.000 482.080 ;
    END
  END w00[15]
  PIN w00[1]
    DIRECTION INPUT ;
    USE SIGNAL ;
    ANTENNAGATEAREA 0.631200 ;
    ANTENNADIFFAREA 0.434700 ;
    PORT
      LAYER met3 ;
        RECT 0.000 348.200 4.000 348.800 ;
    END
  END w00[1]
  PIN w00[2]
    DIRECTION INPUT ;
    USE SIGNAL ;
    ANTENNAGATEAREA 0.631200 ;
    ANTENNADIFFAREA 0.434700 ;
    PORT
      LAYER met3 ;
        RECT 0.000 357.720 4.000 358.320 ;
    END
  END w00[2]
  PIN w00[3]
    DIRECTION INPUT ;
    USE SIGNAL ;
    ANTENNAGATEAREA 0.631200 ;
    ANTENNADIFFAREA 0.434700 ;
    PORT
      LAYER met3 ;
        RECT 0.000 367.240 4.000 367.840 ;
    END
  END w00[3]
  PIN w00[4]
    DIRECTION INPUT ;
    USE SIGNAL ;
    ANTENNAGATEAREA 0.631200 ;
    ANTENNADIFFAREA 0.434700 ;
    PORT
      LAYER met3 ;
        RECT 0.000 376.760 4.000 377.360 ;
    END
  END w00[4]
  PIN w00[5]
    DIRECTION INPUT ;
    USE SIGNAL ;
    ANTENNAGATEAREA 0.631200 ;
    ANTENNADIFFAREA 0.434700 ;
    PORT
      LAYER met3 ;
        RECT 0.000 386.280 4.000 386.880 ;
    END
  END w00[5]
  PIN w00[6]
    DIRECTION INPUT ;
    USE SIGNAL ;
    ANTENNAGATEAREA 0.631200 ;
    ANTENNADIFFAREA 0.434700 ;
    PORT
      LAYER met3 ;
        RECT 0.000 395.800 4.000 396.400 ;
    END
  END w00[6]
  PIN w00[7]
    DIRECTION INPUT ;
    USE SIGNAL ;
    ANTENNAGATEAREA 0.631200 ;
    ANTENNADIFFAREA 0.434700 ;
    PORT
      LAYER met3 ;
        RECT 0.000 405.320 4.000 405.920 ;
    END
  END w00[7]
  PIN w00[8]
    DIRECTION INPUT ;
    USE SIGNAL ;
    ANTENNAGATEAREA 0.631200 ;
    ANTENNADIFFAREA 0.434700 ;
    PORT
      LAYER met3 ;
        RECT 0.000 414.840 4.000 415.440 ;
    END
  END w00[8]
  PIN w00[9]
    DIRECTION INPUT ;
    USE SIGNAL ;
    ANTENNAGATEAREA 0.631200 ;
    ANTENNADIFFAREA 0.434700 ;
    PORT
      LAYER met3 ;
        RECT 0.000 424.360 4.000 424.960 ;
    END
  END w00[9]
  PIN w01[0]
    DIRECTION INPUT ;
    USE SIGNAL ;
    ANTENNAGATEAREA 0.682200 ;
    ANTENNADIFFAREA 0.434700 ;
    PORT
      LAYER met3 ;
        RECT 646.000 111.560 650.000 112.160 ;
    END
  END w01[0]
  PIN w01[10]
    DIRECTION INPUT ;
    USE SIGNAL ;
    ANTENNAGATEAREA 0.682200 ;
    ANTENNADIFFAREA 0.434700 ;
    PORT
      LAYER met3 ;
        RECT 646.000 274.760 650.000 275.360 ;
    END
  END w01[10]
  PIN w01[11]
    DIRECTION INPUT ;
    USE SIGNAL ;
    ANTENNAGATEAREA 0.647700 ;
    ANTENNADIFFAREA 0.434700 ;
    PORT
      LAYER met3 ;
        RECT 646.000 291.080 650.000 291.680 ;
    END
  END w01[11]
  PIN w01[12]
    DIRECTION INPUT ;
    USE SIGNAL ;
    ANTENNAGATEAREA 0.647700 ;
    ANTENNADIFFAREA 0.434700 ;
    PORT
      LAYER met3 ;
        RECT 646.000 307.400 650.000 308.000 ;
    END
  END w01[12]
  PIN w01[13]
    DIRECTION INPUT ;
    USE SIGNAL ;
    ANTENNAGATEAREA 0.647700 ;
    ANTENNADIFFAREA 0.434700 ;
    PORT
      LAYER met3 ;
        RECT 646.000 323.720 650.000 324.320 ;
    END
  END w01[13]
  PIN w01[14]
    DIRECTION INPUT ;
    USE SIGNAL ;
    ANTENNAGATEAREA 0.647700 ;
    ANTENNADIFFAREA 0.434700 ;
    PORT
      LAYER met3 ;
        RECT 646.000 340.040 650.000 340.640 ;
    END
  END w01[14]
  PIN w01[15]
    DIRECTION INPUT ;
    USE SIGNAL ;
    ANTENNAGATEAREA 0.647700 ;
    ANTENNADIFFAREA 0.434700 ;
    PORT
      LAYER met3 ;
        RECT 646.000 356.360 650.000 356.960 ;
    END
  END w01[15]
  PIN w01[1]
    DIRECTION INPUT ;
    USE SIGNAL ;
    ANTENNAGATEAREA 0.682200 ;
    ANTENNADIFFAREA 0.434700 ;
    PORT
      LAYER met3 ;
        RECT 646.000 127.880 650.000 128.480 ;
    END
  END w01[1]
  PIN w01[2]
    DIRECTION INPUT ;
    USE SIGNAL ;
    ANTENNAGATEAREA 0.682200 ;
    ANTENNADIFFAREA 0.434700 ;
    PORT
      LAYER met3 ;
        RECT 646.000 144.200 650.000 144.800 ;
    END
  END w01[2]
  PIN w01[3]
    DIRECTION INPUT ;
    USE SIGNAL ;
    ANTENNAGATEAREA 0.682200 ;
    ANTENNADIFFAREA 0.434700 ;
    PORT
      LAYER met3 ;
        RECT 646.000 160.520 650.000 161.120 ;
    END
  END w01[3]
  PIN w01[4]
    DIRECTION INPUT ;
    USE SIGNAL ;
    ANTENNAGATEAREA 0.682200 ;
    ANTENNADIFFAREA 0.434700 ;
    PORT
      LAYER met3 ;
        RECT 646.000 176.840 650.000 177.440 ;
    END
  END w01[4]
  PIN w01[5]
    DIRECTION INPUT ;
    USE SIGNAL ;
    ANTENNAGATEAREA 0.682200 ;
    ANTENNADIFFAREA 0.434700 ;
    PORT
      LAYER met3 ;
        RECT 646.000 193.160 650.000 193.760 ;
    END
  END w01[5]
  PIN w01[6]
    DIRECTION INPUT ;
    USE SIGNAL ;
    ANTENNAGATEAREA 0.682200 ;
    ANTENNADIFFAREA 0.434700 ;
    PORT
      LAYER met3 ;
        RECT 646.000 209.480 650.000 210.080 ;
    END
  END w01[6]
  PIN w01[7]
    DIRECTION INPUT ;
    USE SIGNAL ;
    ANTENNAGATEAREA 0.682200 ;
    ANTENNADIFFAREA 0.434700 ;
    PORT
      LAYER met3 ;
        RECT 646.000 225.800 650.000 226.400 ;
    END
  END w01[7]
  PIN w01[8]
    DIRECTION INPUT ;
    USE SIGNAL ;
    ANTENNAGATEAREA 0.682200 ;
    ANTENNADIFFAREA 0.434700 ;
    PORT
      LAYER met3 ;
        RECT 646.000 242.120 650.000 242.720 ;
    END
  END w01[8]
  PIN w01[9]
    DIRECTION INPUT ;
    USE SIGNAL ;
    ANTENNAGATEAREA 0.682200 ;
    ANTENNADIFFAREA 0.434700 ;
    PORT
      LAYER met3 ;
        RECT 646.000 258.440 650.000 259.040 ;
    END
  END w01[9]
  PIN w10[0]
    DIRECTION INPUT ;
    USE SIGNAL ;
    ANTENNAGATEAREA 0.647700 ;
    ANTENNADIFFAREA 0.434700 ;
    PORT
      LAYER met3 ;
        RECT 0.000 491.000 4.000 491.600 ;
    END
  END w10[0]
  PIN w10[10]
    DIRECTION INPUT ;
    USE SIGNAL ;
    ANTENNAGATEAREA 0.647700 ;
    ANTENNADIFFAREA 0.434700 ;
    PORT
      LAYER met3 ;
        RECT 0.000 586.200 4.000 586.800 ;
    END
  END w10[10]
  PIN w10[11]
    DIRECTION INPUT ;
    USE SIGNAL ;
    ANTENNAGATEAREA 0.647700 ;
    ANTENNADIFFAREA 0.434700 ;
    PORT
      LAYER met3 ;
        RECT 0.000 595.720 4.000 596.320 ;
    END
  END w10[11]
  PIN w10[12]
    DIRECTION INPUT ;
    USE SIGNAL ;
    ANTENNAGATEAREA 0.647700 ;
    ANTENNADIFFAREA 0.434700 ;
    PORT
      LAYER met3 ;
        RECT 0.000 605.240 4.000 605.840 ;
    END
  END w10[12]
  PIN w10[13]
    DIRECTION INPUT ;
    USE SIGNAL ;
    ANTENNAGATEAREA 0.647700 ;
    ANTENNADIFFAREA 0.434700 ;
    PORT
      LAYER met3 ;
        RECT 0.000 614.760 4.000 615.360 ;
    END
  END w10[13]
  PIN w10[14]
    DIRECTION INPUT ;
    USE SIGNAL ;
    ANTENNAGATEAREA 0.647700 ;
    ANTENNADIFFAREA 0.434700 ;
    PORT
      LAYER met3 ;
        RECT 0.000 624.280 4.000 624.880 ;
    END
  END w10[14]
  PIN w10[15]
    DIRECTION INPUT ;
    USE SIGNAL ;
    ANTENNAGATEAREA 0.647700 ;
    ANTENNADIFFAREA 0.434700 ;
    PORT
      LAYER met3 ;
        RECT 0.000 633.800 4.000 634.400 ;
    END
  END w10[15]
  PIN w10[1]
    DIRECTION INPUT ;
    USE SIGNAL ;
    ANTENNAGATEAREA 0.647700 ;
    ANTENNADIFFAREA 0.434700 ;
    PORT
      LAYER met3 ;
        RECT 0.000 500.520 4.000 501.120 ;
    END
  END w10[1]
  PIN w10[2]
    DIRECTION INPUT ;
    USE SIGNAL ;
    ANTENNAGATEAREA 0.647700 ;
    ANTENNADIFFAREA 0.434700 ;
    PORT
      LAYER met3 ;
        RECT 0.000 510.040 4.000 510.640 ;
    END
  END w10[2]
  PIN w10[3]
    DIRECTION INPUT ;
    USE SIGNAL ;
    ANTENNAGATEAREA 0.647700 ;
    ANTENNADIFFAREA 0.434700 ;
    PORT
      LAYER met3 ;
        RECT 0.000 519.560 4.000 520.160 ;
    END
  END w10[3]
  PIN w10[4]
    DIRECTION INPUT ;
    USE SIGNAL ;
    ANTENNAGATEAREA 0.647700 ;
    ANTENNADIFFAREA 0.434700 ;
    PORT
      LAYER met3 ;
        RECT 0.000 529.080 4.000 529.680 ;
    END
  END w10[4]
  PIN w10[5]
    DIRECTION INPUT ;
    USE SIGNAL ;
    ANTENNAGATEAREA 0.647700 ;
    ANTENNADIFFAREA 0.434700 ;
    PORT
      LAYER met3 ;
        RECT 0.000 538.600 4.000 539.200 ;
    END
  END w10[5]
  PIN w10[6]
    DIRECTION INPUT ;
    USE SIGNAL ;
    ANTENNAGATEAREA 0.647700 ;
    ANTENNADIFFAREA 0.434700 ;
    PORT
      LAYER met3 ;
        RECT 0.000 548.120 4.000 548.720 ;
    END
  END w10[6]
  PIN w10[7]
    DIRECTION INPUT ;
    USE SIGNAL ;
    ANTENNAGATEAREA 0.647700 ;
    ANTENNADIFFAREA 0.434700 ;
    PORT
      LAYER met3 ;
        RECT 0.000 557.640 4.000 558.240 ;
    END
  END w10[7]
  PIN w10[8]
    DIRECTION INPUT ;
    USE SIGNAL ;
    ANTENNAGATEAREA 0.647700 ;
    ANTENNADIFFAREA 0.434700 ;
    PORT
      LAYER met3 ;
        RECT 0.000 567.160 4.000 567.760 ;
    END
  END w10[8]
  PIN w10[9]
    DIRECTION INPUT ;
    USE SIGNAL ;
    ANTENNAGATEAREA 0.647700 ;
    ANTENNADIFFAREA 0.434700 ;
    PORT
      LAYER met3 ;
        RECT 0.000 576.680 4.000 577.280 ;
    END
  END w10[9]
  PIN w11[0]
    DIRECTION INPUT ;
    USE SIGNAL ;
    ANTENNAGATEAREA 0.682200 ;
    ANTENNADIFFAREA 0.434700 ;
    PORT
      LAYER met3 ;
        RECT 646.000 372.680 650.000 373.280 ;
    END
  END w11[0]
  PIN w11[10]
    DIRECTION INPUT ;
    USE SIGNAL ;
    ANTENNAGATEAREA 0.860700 ;
    ANTENNADIFFAREA 0.434700 ;
    PORT
      LAYER met3 ;
        RECT 646.000 535.880 650.000 536.480 ;
    END
  END w11[10]
  PIN w11[11]
    DIRECTION INPUT ;
    USE SIGNAL ;
    ANTENNAGATEAREA 0.860700 ;
    ANTENNADIFFAREA 0.434700 ;
    PORT
      LAYER met3 ;
        RECT 646.000 552.200 650.000 552.800 ;
    END
  END w11[11]
  PIN w11[12]
    DIRECTION INPUT ;
    USE SIGNAL ;
    ANTENNAGATEAREA 0.860700 ;
    ANTENNADIFFAREA 0.434700 ;
    PORT
      LAYER met3 ;
        RECT 646.000 568.520 650.000 569.120 ;
    END
  END w11[12]
  PIN w11[13]
    DIRECTION INPUT ;
    USE SIGNAL ;
    ANTENNAGATEAREA 0.860700 ;
    ANTENNADIFFAREA 0.434700 ;
    PORT
      LAYER met3 ;
        RECT 646.000 584.840 650.000 585.440 ;
    END
  END w11[13]
  PIN w11[14]
    DIRECTION INPUT ;
    USE SIGNAL ;
    ANTENNAGATEAREA 0.860700 ;
    ANTENNADIFFAREA 0.434700 ;
    PORT
      LAYER met3 ;
        RECT 646.000 601.160 650.000 601.760 ;
    END
  END w11[14]
  PIN w11[15]
    DIRECTION INPUT ;
    USE SIGNAL ;
    ANTENNAGATEAREA 0.860700 ;
    ANTENNADIFFAREA 0.434700 ;
    PORT
      LAYER met3 ;
        RECT 646.000 617.480 650.000 618.080 ;
    END
  END w11[15]
  PIN w11[1]
    DIRECTION INPUT ;
    USE SIGNAL ;
    ANTENNAGATEAREA 0.682200 ;
    ANTENNADIFFAREA 0.434700 ;
    PORT
      LAYER met3 ;
        RECT 646.000 389.000 650.000 389.600 ;
    END
  END w11[1]
  PIN w11[2]
    DIRECTION INPUT ;
    USE SIGNAL ;
    ANTENNAGATEAREA 0.682200 ;
    ANTENNADIFFAREA 0.434700 ;
    PORT
      LAYER met3 ;
        RECT 646.000 405.320 650.000 405.920 ;
    END
  END w11[2]
  PIN w11[3]
    DIRECTION INPUT ;
    USE SIGNAL ;
    ANTENNAGATEAREA 0.682200 ;
    ANTENNADIFFAREA 0.434700 ;
    PORT
      LAYER met3 ;
        RECT 646.000 421.640 650.000 422.240 ;
    END
  END w11[3]
  PIN w11[4]
    DIRECTION INPUT ;
    USE SIGNAL ;
    ANTENNAGATEAREA 0.682200 ;
    ANTENNADIFFAREA 0.434700 ;
    PORT
      LAYER met3 ;
        RECT 646.000 437.960 650.000 438.560 ;
    END
  END w11[4]
  PIN w11[5]
    DIRECTION INPUT ;
    USE SIGNAL ;
    ANTENNAGATEAREA 0.682200 ;
    ANTENNADIFFAREA 0.434700 ;
    PORT
      LAYER met3 ;
        RECT 646.000 454.280 650.000 454.880 ;
    END
  END w11[5]
  PIN w11[6]
    DIRECTION INPUT ;
    USE SIGNAL ;
    ANTENNAGATEAREA 0.682200 ;
    ANTENNADIFFAREA 0.434700 ;
    PORT
      LAYER met3 ;
        RECT 646.000 470.600 650.000 471.200 ;
    END
  END w11[6]
  PIN w11[7]
    DIRECTION INPUT ;
    USE SIGNAL ;
    ANTENNAGATEAREA 0.682200 ;
    ANTENNADIFFAREA 0.434700 ;
    PORT
      LAYER met3 ;
        RECT 646.000 486.920 650.000 487.520 ;
    END
  END w11[7]
  PIN w11[8]
    DIRECTION INPUT ;
    USE SIGNAL ;
    ANTENNAGATEAREA 0.860700 ;
    ANTENNADIFFAREA 0.434700 ;
    PORT
      LAYER met3 ;
        RECT 646.000 503.240 650.000 503.840 ;
    END
  END w11[8]
  PIN w11[9]
    DIRECTION INPUT ;
    USE SIGNAL ;
    ANTENNAGATEAREA 0.860700 ;
    ANTENNADIFFAREA 0.434700 ;
    PORT
      LAYER met3 ;
        RECT 646.000 519.560 650.000 520.160 ;
    END
  END w11[9]
  OBS
      LAYER li1 ;
        RECT 15.180 16.235 634.800 633.845 ;
      LAYER met1 ;
        RECT 6.050 16.080 643.930 634.400 ;
      LAYER met2 ;
        RECT 6.630 645.720 15.910 646.410 ;
        RECT 16.750 645.720 26.030 646.410 ;
        RECT 26.870 645.720 36.150 646.410 ;
        RECT 36.990 645.720 46.270 646.410 ;
        RECT 47.110 645.720 56.390 646.410 ;
        RECT 57.230 645.720 66.510 646.410 ;
        RECT 67.350 645.720 76.630 646.410 ;
        RECT 77.470 645.720 86.750 646.410 ;
        RECT 87.590 645.720 96.870 646.410 ;
        RECT 97.710 645.720 106.990 646.410 ;
        RECT 107.830 645.720 117.110 646.410 ;
        RECT 117.950 645.720 127.230 646.410 ;
        RECT 128.070 645.720 137.350 646.410 ;
        RECT 138.190 645.720 147.470 646.410 ;
        RECT 148.310 645.720 157.590 646.410 ;
        RECT 158.430 645.720 167.710 646.410 ;
        RECT 168.550 645.720 177.830 646.410 ;
        RECT 178.670 645.720 187.950 646.410 ;
        RECT 188.790 645.720 198.070 646.410 ;
        RECT 198.910 645.720 208.190 646.410 ;
        RECT 209.030 645.720 218.310 646.410 ;
        RECT 219.150 645.720 228.430 646.410 ;
        RECT 229.270 645.720 238.550 646.410 ;
        RECT 239.390 645.720 248.670 646.410 ;
        RECT 249.510 645.720 258.790 646.410 ;
        RECT 259.630 645.720 268.910 646.410 ;
        RECT 269.750 645.720 279.030 646.410 ;
        RECT 279.870 645.720 289.150 646.410 ;
        RECT 289.990 645.720 299.270 646.410 ;
        RECT 300.110 645.720 309.390 646.410 ;
        RECT 310.230 645.720 319.510 646.410 ;
        RECT 320.350 645.720 329.630 646.410 ;
        RECT 330.470 645.720 339.750 646.410 ;
        RECT 340.590 645.720 349.870 646.410 ;
        RECT 350.710 645.720 359.990 646.410 ;
        RECT 360.830 645.720 370.110 646.410 ;
        RECT 370.950 645.720 380.230 646.410 ;
        RECT 381.070 645.720 390.350 646.410 ;
        RECT 391.190 645.720 400.470 646.410 ;
        RECT 401.310 645.720 410.590 646.410 ;
        RECT 411.430 645.720 420.710 646.410 ;
        RECT 421.550 645.720 430.830 646.410 ;
        RECT 431.670 645.720 440.950 646.410 ;
        RECT 441.790 645.720 451.070 646.410 ;
        RECT 451.910 645.720 461.190 646.410 ;
        RECT 462.030 645.720 471.310 646.410 ;
        RECT 472.150 645.720 481.430 646.410 ;
        RECT 482.270 645.720 491.550 646.410 ;
        RECT 492.390 645.720 501.670 646.410 ;
        RECT 502.510 645.720 511.790 646.410 ;
        RECT 512.630 645.720 521.910 646.410 ;
        RECT 522.750 645.720 532.030 646.410 ;
        RECT 532.870 645.720 542.150 646.410 ;
        RECT 542.990 645.720 552.270 646.410 ;
        RECT 553.110 645.720 562.390 646.410 ;
        RECT 563.230 645.720 572.510 646.410 ;
        RECT 573.350 645.720 582.630 646.410 ;
        RECT 583.470 645.720 592.750 646.410 ;
        RECT 593.590 645.720 602.870 646.410 ;
        RECT 603.710 645.720 612.990 646.410 ;
        RECT 613.830 645.720 623.110 646.410 ;
        RECT 623.950 645.720 633.230 646.410 ;
        RECT 634.070 645.720 643.350 646.410 ;
        RECT 6.080 4.280 643.900 645.720 ;
        RECT 6.630 3.670 15.910 4.280 ;
        RECT 16.750 3.670 26.030 4.280 ;
        RECT 26.870 3.670 36.150 4.280 ;
        RECT 36.990 3.670 46.270 4.280 ;
        RECT 47.110 3.670 56.390 4.280 ;
        RECT 57.230 3.670 66.510 4.280 ;
        RECT 67.350 3.670 76.630 4.280 ;
        RECT 77.470 3.670 86.750 4.280 ;
        RECT 87.590 3.670 96.870 4.280 ;
        RECT 97.710 3.670 106.990 4.280 ;
        RECT 107.830 3.670 117.110 4.280 ;
        RECT 117.950 3.670 127.230 4.280 ;
        RECT 128.070 3.670 137.350 4.280 ;
        RECT 138.190 3.670 147.470 4.280 ;
        RECT 148.310 3.670 157.590 4.280 ;
        RECT 158.430 3.670 167.710 4.280 ;
        RECT 168.550 3.670 177.830 4.280 ;
        RECT 178.670 3.670 187.950 4.280 ;
        RECT 188.790 3.670 198.070 4.280 ;
        RECT 198.910 3.670 208.190 4.280 ;
        RECT 209.030 3.670 218.310 4.280 ;
        RECT 219.150 3.670 228.430 4.280 ;
        RECT 229.270 3.670 238.550 4.280 ;
        RECT 239.390 3.670 248.670 4.280 ;
        RECT 249.510 3.670 258.790 4.280 ;
        RECT 259.630 3.670 268.910 4.280 ;
        RECT 269.750 3.670 279.030 4.280 ;
        RECT 279.870 3.670 289.150 4.280 ;
        RECT 289.990 3.670 299.270 4.280 ;
        RECT 300.110 3.670 309.390 4.280 ;
        RECT 310.230 3.670 319.510 4.280 ;
        RECT 320.350 3.670 329.630 4.280 ;
        RECT 330.470 3.670 339.750 4.280 ;
        RECT 340.590 3.670 349.870 4.280 ;
        RECT 350.710 3.670 359.990 4.280 ;
        RECT 360.830 3.670 370.110 4.280 ;
        RECT 370.950 3.670 380.230 4.280 ;
        RECT 381.070 3.670 390.350 4.280 ;
        RECT 391.190 3.670 400.470 4.280 ;
        RECT 401.310 3.670 410.590 4.280 ;
        RECT 411.430 3.670 420.710 4.280 ;
        RECT 421.550 3.670 430.830 4.280 ;
        RECT 431.670 3.670 440.950 4.280 ;
        RECT 441.790 3.670 451.070 4.280 ;
        RECT 451.910 3.670 461.190 4.280 ;
        RECT 462.030 3.670 471.310 4.280 ;
        RECT 472.150 3.670 481.430 4.280 ;
        RECT 482.270 3.670 491.550 4.280 ;
        RECT 492.390 3.670 501.670 4.280 ;
        RECT 502.510 3.670 511.790 4.280 ;
        RECT 512.630 3.670 521.910 4.280 ;
        RECT 522.750 3.670 532.030 4.280 ;
        RECT 532.870 3.670 542.150 4.280 ;
        RECT 542.990 3.670 552.270 4.280 ;
        RECT 553.110 3.670 562.390 4.280 ;
        RECT 563.230 3.670 572.510 4.280 ;
        RECT 573.350 3.670 582.630 4.280 ;
        RECT 583.470 3.670 592.750 4.280 ;
        RECT 593.590 3.670 602.870 4.280 ;
        RECT 603.710 3.670 612.990 4.280 ;
        RECT 613.830 3.670 623.110 4.280 ;
        RECT 623.950 3.670 633.230 4.280 ;
        RECT 634.070 3.670 643.350 4.280 ;
      LAYER met3 ;
        RECT 4.400 633.400 646.000 634.265 ;
        RECT 4.000 625.280 646.000 633.400 ;
        RECT 4.400 623.880 646.000 625.280 ;
        RECT 4.000 618.480 646.000 623.880 ;
        RECT 4.000 617.080 645.600 618.480 ;
        RECT 4.000 615.760 646.000 617.080 ;
        RECT 4.400 614.360 646.000 615.760 ;
        RECT 4.000 606.240 646.000 614.360 ;
        RECT 4.400 604.840 646.000 606.240 ;
        RECT 4.000 602.160 646.000 604.840 ;
        RECT 4.000 600.760 645.600 602.160 ;
        RECT 4.000 596.720 646.000 600.760 ;
        RECT 4.400 595.320 646.000 596.720 ;
        RECT 4.000 587.200 646.000 595.320 ;
        RECT 4.400 585.840 646.000 587.200 ;
        RECT 4.400 585.800 645.600 585.840 ;
        RECT 4.000 584.440 645.600 585.800 ;
        RECT 4.000 577.680 646.000 584.440 ;
        RECT 4.400 576.280 646.000 577.680 ;
        RECT 4.000 569.520 646.000 576.280 ;
        RECT 4.000 568.160 645.600 569.520 ;
        RECT 4.400 568.120 645.600 568.160 ;
        RECT 4.400 566.760 646.000 568.120 ;
        RECT 4.000 558.640 646.000 566.760 ;
        RECT 4.400 557.240 646.000 558.640 ;
        RECT 4.000 553.200 646.000 557.240 ;
        RECT 4.000 551.800 645.600 553.200 ;
        RECT 4.000 549.120 646.000 551.800 ;
        RECT 4.400 547.720 646.000 549.120 ;
        RECT 4.000 539.600 646.000 547.720 ;
        RECT 4.400 538.200 646.000 539.600 ;
        RECT 4.000 536.880 646.000 538.200 ;
        RECT 4.000 535.480 645.600 536.880 ;
        RECT 4.000 530.080 646.000 535.480 ;
        RECT 4.400 528.680 646.000 530.080 ;
        RECT 4.000 520.560 646.000 528.680 ;
        RECT 4.400 519.160 645.600 520.560 ;
        RECT 4.000 511.040 646.000 519.160 ;
        RECT 4.400 509.640 646.000 511.040 ;
        RECT 4.000 504.240 646.000 509.640 ;
        RECT 4.000 502.840 645.600 504.240 ;
        RECT 4.000 501.520 646.000 502.840 ;
        RECT 4.400 500.120 646.000 501.520 ;
        RECT 4.000 492.000 646.000 500.120 ;
        RECT 4.400 490.600 646.000 492.000 ;
        RECT 4.000 487.920 646.000 490.600 ;
        RECT 4.000 486.520 645.600 487.920 ;
        RECT 4.000 482.480 646.000 486.520 ;
        RECT 4.400 481.080 646.000 482.480 ;
        RECT 4.000 472.960 646.000 481.080 ;
        RECT 4.400 471.600 646.000 472.960 ;
        RECT 4.400 471.560 645.600 471.600 ;
        RECT 4.000 470.200 645.600 471.560 ;
        RECT 4.000 463.440 646.000 470.200 ;
        RECT 4.400 462.040 646.000 463.440 ;
        RECT 4.000 455.280 646.000 462.040 ;
        RECT 4.000 453.920 645.600 455.280 ;
        RECT 4.400 453.880 645.600 453.920 ;
        RECT 4.400 452.520 646.000 453.880 ;
        RECT 4.000 444.400 646.000 452.520 ;
        RECT 4.400 443.000 646.000 444.400 ;
        RECT 4.000 438.960 646.000 443.000 ;
        RECT 4.000 437.560 645.600 438.960 ;
        RECT 4.000 434.880 646.000 437.560 ;
        RECT 4.400 433.480 646.000 434.880 ;
        RECT 4.000 425.360 646.000 433.480 ;
        RECT 4.400 423.960 646.000 425.360 ;
        RECT 4.000 422.640 646.000 423.960 ;
        RECT 4.000 421.240 645.600 422.640 ;
        RECT 4.000 415.840 646.000 421.240 ;
        RECT 4.400 414.440 646.000 415.840 ;
        RECT 4.000 406.320 646.000 414.440 ;
        RECT 4.400 404.920 645.600 406.320 ;
        RECT 4.000 396.800 646.000 404.920 ;
        RECT 4.400 395.400 646.000 396.800 ;
        RECT 4.000 390.000 646.000 395.400 ;
        RECT 4.000 388.600 645.600 390.000 ;
        RECT 4.000 387.280 646.000 388.600 ;
        RECT 4.400 385.880 646.000 387.280 ;
        RECT 4.000 377.760 646.000 385.880 ;
        RECT 4.400 376.360 646.000 377.760 ;
        RECT 4.000 373.680 646.000 376.360 ;
        RECT 4.000 372.280 645.600 373.680 ;
        RECT 4.000 368.240 646.000 372.280 ;
        RECT 4.400 366.840 646.000 368.240 ;
        RECT 4.000 358.720 646.000 366.840 ;
        RECT 4.400 357.360 646.000 358.720 ;
        RECT 4.400 357.320 645.600 357.360 ;
        RECT 4.000 355.960 645.600 357.320 ;
        RECT 4.000 349.200 646.000 355.960 ;
        RECT 4.400 347.800 646.000 349.200 ;
        RECT 4.000 341.040 646.000 347.800 ;
        RECT 4.000 339.680 645.600 341.040 ;
        RECT 4.400 339.640 645.600 339.680 ;
        RECT 4.400 338.280 646.000 339.640 ;
        RECT 4.000 330.160 646.000 338.280 ;
        RECT 4.400 328.760 646.000 330.160 ;
        RECT 4.000 324.720 646.000 328.760 ;
        RECT 4.000 323.320 645.600 324.720 ;
        RECT 4.000 320.640 646.000 323.320 ;
        RECT 4.400 319.240 646.000 320.640 ;
        RECT 4.000 311.120 646.000 319.240 ;
        RECT 4.400 309.720 646.000 311.120 ;
        RECT 4.000 308.400 646.000 309.720 ;
        RECT 4.000 307.000 645.600 308.400 ;
        RECT 4.000 301.600 646.000 307.000 ;
        RECT 4.400 300.200 646.000 301.600 ;
        RECT 4.000 292.080 646.000 300.200 ;
        RECT 4.400 290.680 645.600 292.080 ;
        RECT 4.000 282.560 646.000 290.680 ;
        RECT 4.400 281.160 646.000 282.560 ;
        RECT 4.000 275.760 646.000 281.160 ;
        RECT 4.000 274.360 645.600 275.760 ;
        RECT 4.000 273.040 646.000 274.360 ;
        RECT 4.400 271.640 646.000 273.040 ;
        RECT 4.000 263.520 646.000 271.640 ;
        RECT 4.400 262.120 646.000 263.520 ;
        RECT 4.000 259.440 646.000 262.120 ;
        RECT 4.000 258.040 645.600 259.440 ;
        RECT 4.000 254.000 646.000 258.040 ;
        RECT 4.400 252.600 646.000 254.000 ;
        RECT 4.000 244.480 646.000 252.600 ;
        RECT 4.400 243.120 646.000 244.480 ;
        RECT 4.400 243.080 645.600 243.120 ;
        RECT 4.000 241.720 645.600 243.080 ;
        RECT 4.000 234.960 646.000 241.720 ;
        RECT 4.400 233.560 646.000 234.960 ;
        RECT 4.000 226.800 646.000 233.560 ;
        RECT 4.000 225.440 645.600 226.800 ;
        RECT 4.400 225.400 645.600 225.440 ;
        RECT 4.400 224.040 646.000 225.400 ;
        RECT 4.000 215.920 646.000 224.040 ;
        RECT 4.400 214.520 646.000 215.920 ;
        RECT 4.000 210.480 646.000 214.520 ;
        RECT 4.000 209.080 645.600 210.480 ;
        RECT 4.000 206.400 646.000 209.080 ;
        RECT 4.400 205.000 646.000 206.400 ;
        RECT 4.000 196.880 646.000 205.000 ;
        RECT 4.400 195.480 646.000 196.880 ;
        RECT 4.000 194.160 646.000 195.480 ;
        RECT 4.000 192.760 645.600 194.160 ;
        RECT 4.000 187.360 646.000 192.760 ;
        RECT 4.400 185.960 646.000 187.360 ;
        RECT 4.000 177.840 646.000 185.960 ;
        RECT 4.400 176.440 645.600 177.840 ;
        RECT 4.000 168.320 646.000 176.440 ;
        RECT 4.400 166.920 646.000 168.320 ;
        RECT 4.000 161.520 646.000 166.920 ;
        RECT 4.000 160.120 645.600 161.520 ;
        RECT 4.000 158.800 646.000 160.120 ;
        RECT 4.400 157.400 646.000 158.800 ;
        RECT 4.000 149.280 646.000 157.400 ;
        RECT 4.400 147.880 646.000 149.280 ;
        RECT 4.000 145.200 646.000 147.880 ;
        RECT 4.000 143.800 645.600 145.200 ;
        RECT 4.000 139.760 646.000 143.800 ;
        RECT 4.400 138.360 646.000 139.760 ;
        RECT 4.000 130.240 646.000 138.360 ;
        RECT 4.400 128.880 646.000 130.240 ;
        RECT 4.400 128.840 645.600 128.880 ;
        RECT 4.000 127.480 645.600 128.840 ;
        RECT 4.000 120.720 646.000 127.480 ;
        RECT 4.400 119.320 646.000 120.720 ;
        RECT 4.000 112.560 646.000 119.320 ;
        RECT 4.000 111.200 645.600 112.560 ;
        RECT 4.400 111.160 645.600 111.200 ;
        RECT 4.400 109.800 646.000 111.160 ;
        RECT 4.000 101.680 646.000 109.800 ;
        RECT 4.400 100.280 646.000 101.680 ;
        RECT 4.000 96.240 646.000 100.280 ;
        RECT 4.000 94.840 645.600 96.240 ;
        RECT 4.000 92.160 646.000 94.840 ;
        RECT 4.400 90.760 646.000 92.160 ;
        RECT 4.000 82.640 646.000 90.760 ;
        RECT 4.400 81.240 646.000 82.640 ;
        RECT 4.000 79.920 646.000 81.240 ;
        RECT 4.000 78.520 645.600 79.920 ;
        RECT 4.000 73.120 646.000 78.520 ;
        RECT 4.400 71.720 646.000 73.120 ;
        RECT 4.000 63.600 646.000 71.720 ;
        RECT 4.400 62.200 645.600 63.600 ;
        RECT 4.000 54.080 646.000 62.200 ;
        RECT 4.400 52.680 646.000 54.080 ;
        RECT 4.000 47.280 646.000 52.680 ;
        RECT 4.000 45.880 645.600 47.280 ;
        RECT 4.000 44.560 646.000 45.880 ;
        RECT 4.400 43.160 646.000 44.560 ;
        RECT 4.000 35.040 646.000 43.160 ;
        RECT 4.400 33.640 646.000 35.040 ;
        RECT 4.000 30.960 646.000 33.640 ;
        RECT 4.000 29.560 645.600 30.960 ;
        RECT 4.000 25.520 646.000 29.560 ;
        RECT 4.400 24.120 646.000 25.520 ;
        RECT 4.000 16.000 646.000 24.120 ;
        RECT 4.400 15.135 646.000 16.000 ;
      LAYER met4 ;
        RECT 17.775 30.095 30.300 607.745 ;
        RECT 32.700 30.095 33.600 607.745 ;
        RECT 36.000 571.705 183.900 607.745 ;
        RECT 186.300 571.705 187.200 607.745 ;
        RECT 189.600 590.880 337.500 607.745 ;
        RECT 189.600 571.705 300.100 590.880 ;
        RECT 36.000 351.735 300.100 571.705 ;
        RECT 36.000 281.705 183.900 351.735 ;
        RECT 186.300 281.705 187.200 351.735 ;
        RECT 189.600 325.760 300.100 351.735 ;
        RECT 302.500 325.760 303.780 590.880 ;
        RECT 306.180 571.705 337.500 590.880 ;
        RECT 339.900 571.705 340.800 607.745 ;
        RECT 343.200 571.705 491.100 607.745 ;
        RECT 493.500 571.705 494.400 607.745 ;
        RECT 496.800 571.705 569.185 607.745 ;
        RECT 306.180 351.735 569.185 571.705 ;
        RECT 306.180 325.760 337.500 351.735 ;
        RECT 189.600 302.560 337.500 325.760 ;
        RECT 189.600 281.705 300.100 302.560 ;
        RECT 36.000 61.735 300.100 281.705 ;
        RECT 36.000 30.095 183.900 61.735 ;
        RECT 186.300 30.095 187.200 61.735 ;
        RECT 189.600 34.720 300.100 61.735 ;
        RECT 302.500 34.720 303.780 302.560 ;
        RECT 306.180 281.705 337.500 302.560 ;
        RECT 339.900 281.705 340.800 351.735 ;
        RECT 343.200 281.705 491.100 351.735 ;
        RECT 493.500 281.705 494.400 351.735 ;
        RECT 496.800 281.705 569.185 351.735 ;
        RECT 306.180 61.735 569.185 281.705 ;
        RECT 306.180 34.720 337.500 61.735 ;
        RECT 189.600 30.095 337.500 34.720 ;
        RECT 339.900 30.095 340.800 61.735 ;
        RECT 343.200 30.095 491.100 61.735 ;
        RECT 493.500 30.095 494.400 61.735 ;
        RECT 496.800 30.095 569.185 61.735 ;
      LAYER met5 ;
        RECT 52.100 345.030 318.660 376.500 ;
        RECT 52.100 191.850 318.660 336.930 ;
        RECT 52.100 68.900 318.660 183.750 ;
  END
END systolic_array_2x2
END LIBRARY

